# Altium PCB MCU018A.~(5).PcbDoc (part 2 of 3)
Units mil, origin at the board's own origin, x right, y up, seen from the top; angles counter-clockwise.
Board outline 4035 x 4400 mil, 2 copper layers (Top Layer, Bottom Layer), stack 62 mil thick; 269 components, 230 nets, 958 pads, 568 vias.

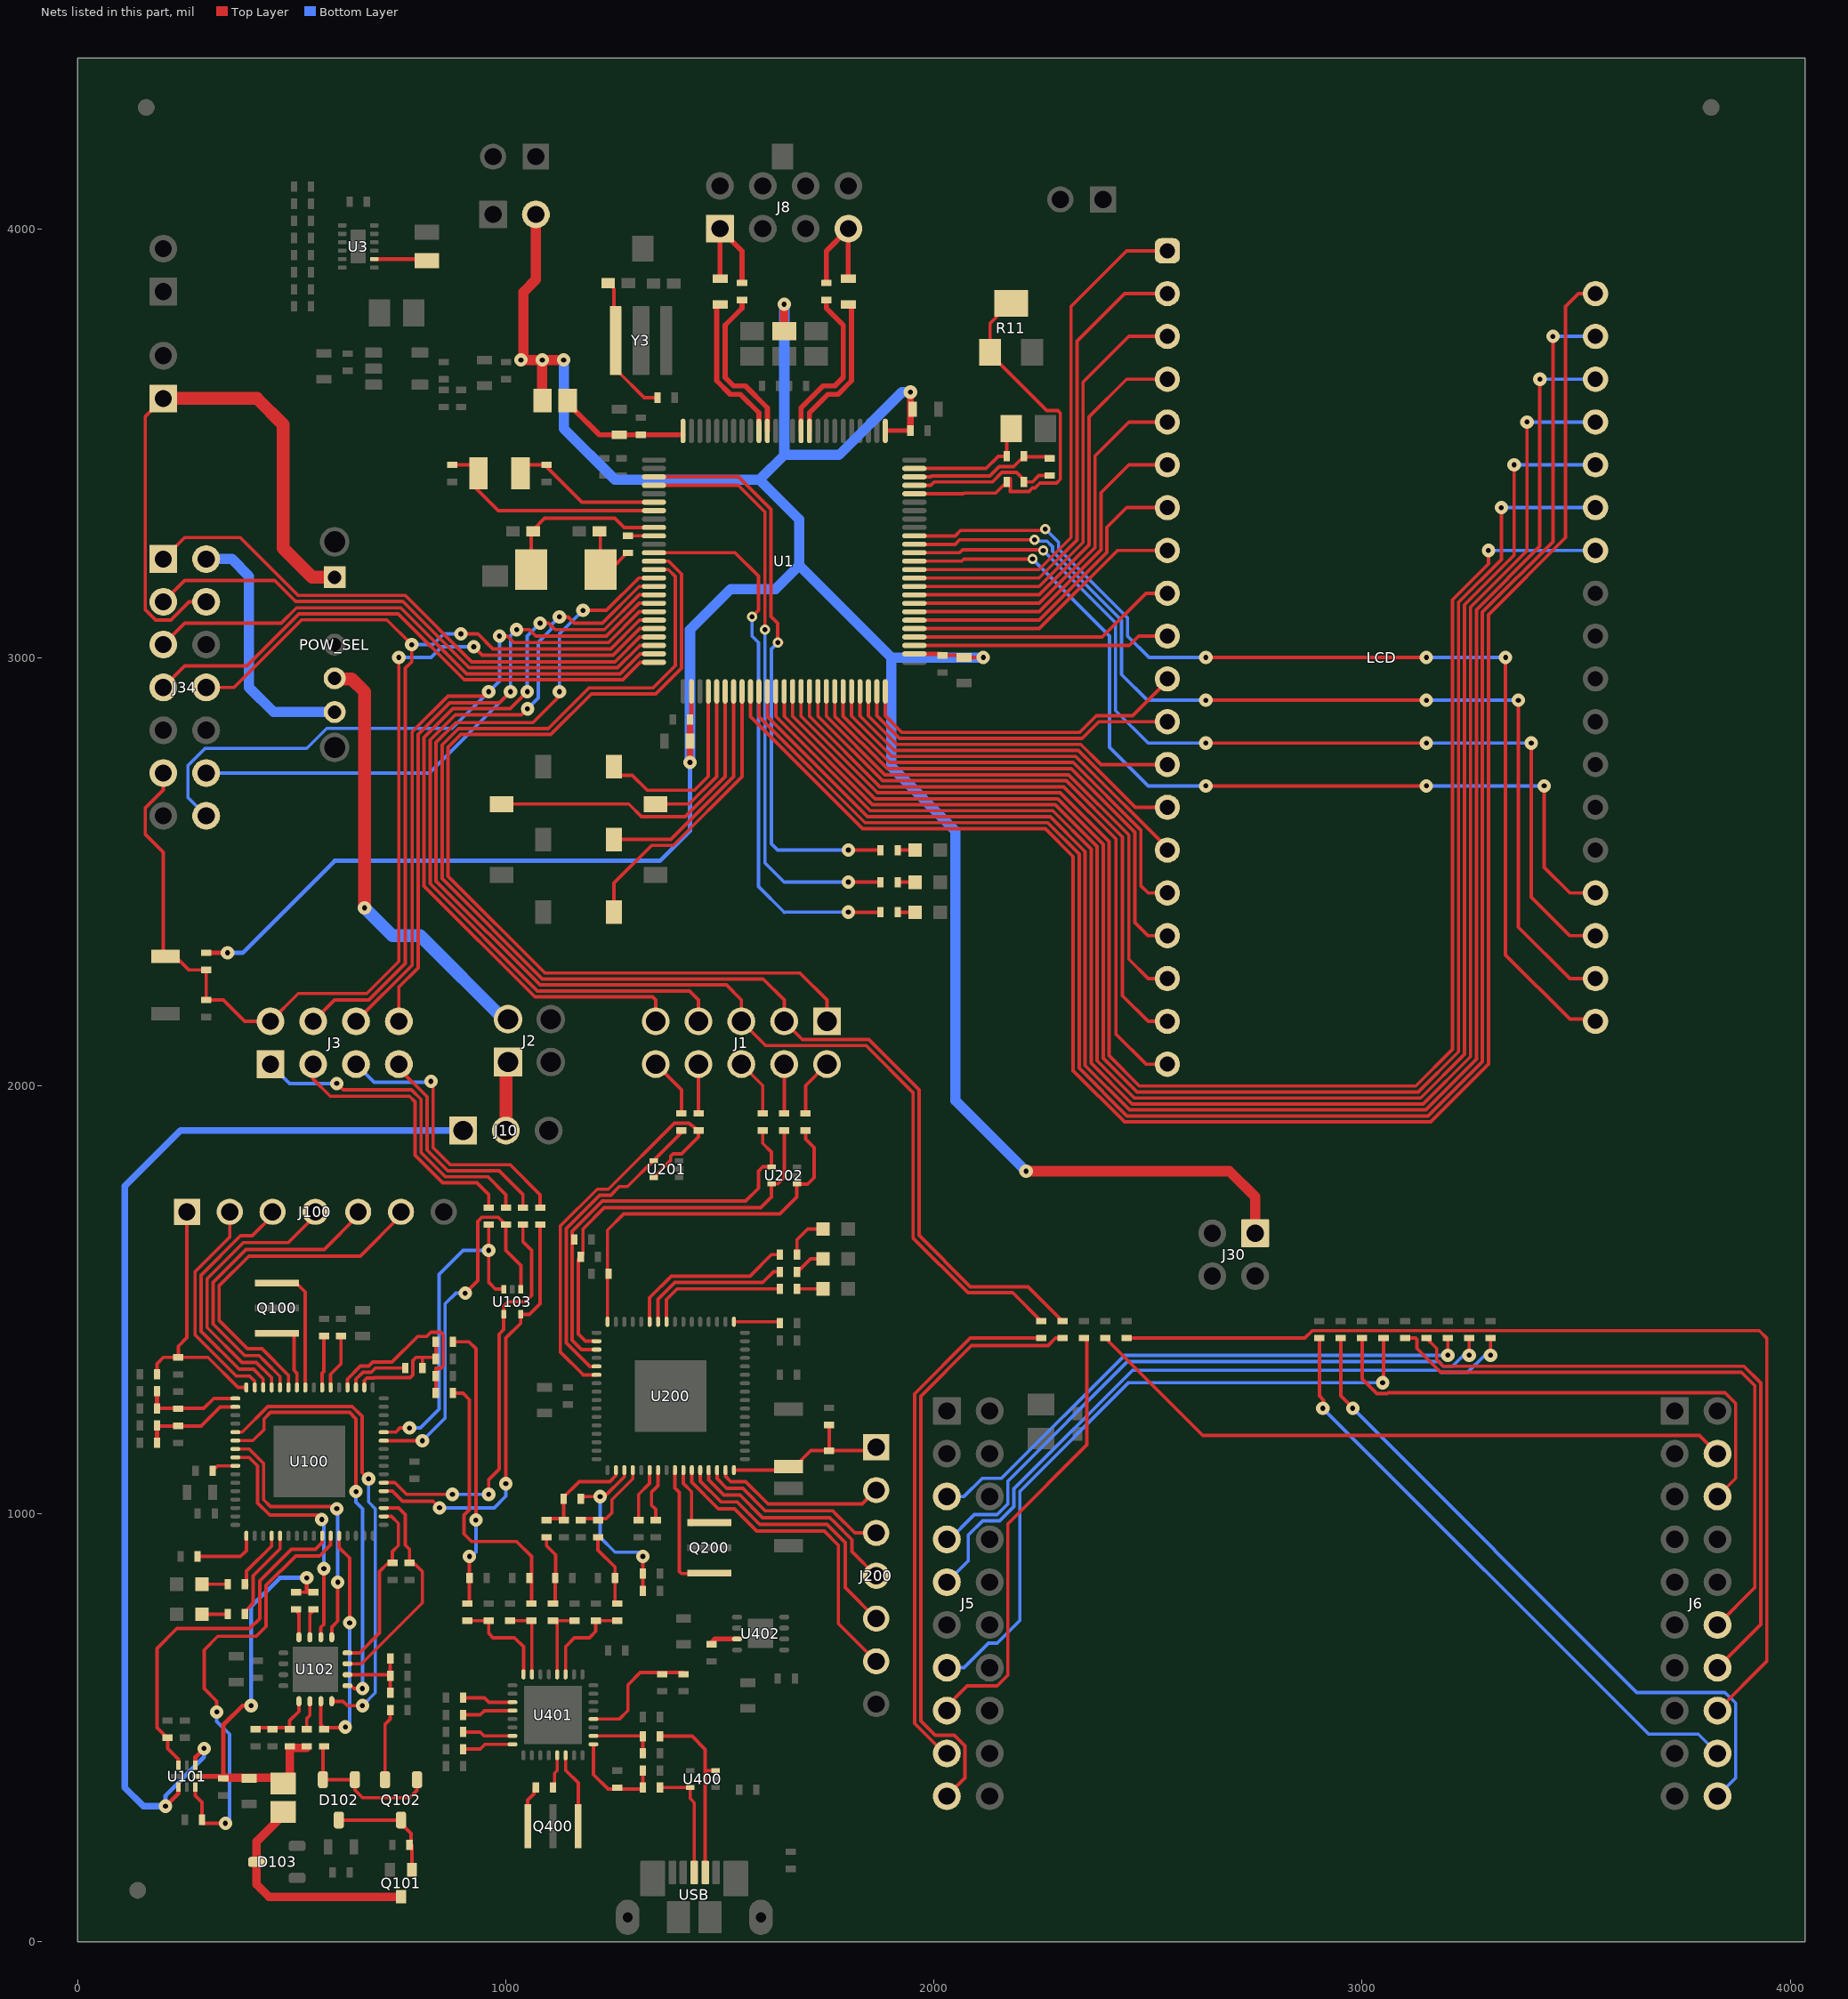
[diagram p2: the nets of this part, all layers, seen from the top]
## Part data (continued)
R15 R26 R100 R101 R201 R203: "RES, 22, 5%, 0.063 W, 0402", Manufacturer=Vishay-Dale, Power_W=0.063, Supplier Part Number 1=541-22JCT-ND, TempCo="200 ppm/C", Tolerance_%=5, Value1=5%, Value2=0.063W, Value_Code=22R0, ValueDisplayed=22
R16 R17: "RES, 200, 1%, 0.063 W, 0402", Manufacturer=Vishay-Dale, Power_W=0.063, Supplier Part Number 1=541-200LCT-ND, TempCo="100 ppm/C", Tolerance_%=1, Value1=1%, Value2=0.063W, Value_Code=200R, ValueDisplayed=200
R18 R121 R123: "RES, 47 k, 5%, 0.063 W, 0402", Manufacturer=Vishay-Dale, Power_W=0.063, Supplier Part Number 1=541-47KJCT-ND, TempCo="200 ppm/C", Tolerance_%=5, Value1=5%, Value2=0.063W, Value_Code=47k0, ValueDisplayed=47k
R19: "RES, 0, 5%, 0.125 W, 0805", Manufacturer=Vishay-Dale, Power_W=0.125, Supplier Part Number 1=541-0.0ACT-ND, TempCo="200 ppm/C", Tolerance_%=5, Value1=5%, Value2=0.125W, Value_Code=0000, ValueDisplayed=0
R20 R21 R22 R41 R42 R43 R44 R45 R46 R47 R48 R49: library part Resistor, "RES, xxx ohm, x%, xW, [PackageReference]", Alternate Manufacturer=-
R23 R24: "RES, 390, 5%, 0.063 W, 0402", Manufacturer=Vishay-Dale, Power_W=0.063, Supplier Part Number 1=541-390JCT-ND, TempCo="200 ppm/C", Tolerance_%=5, Value1=5%, Value2=0.063W, Value_Code=390R, ValueDisplayed=390
R25 R120 R205: "RES, 470, 5%, 0.063 W, 0402", Manufacturer=Vishay-Dale, Power_W=0.063, Supplier Part Number 1=541-470JCT-ND, TempCo="200 ppm/C", Tolerance_%=5, Value1=5%, Value2=0.063W, Value_Code=470R, ValueDisplayed=470
R27 R28 R29 R30 R31 R32 R33 R34 R35 R36 R37 R38 R50 R51 R124: "RES, 0, 5%, 0.063 W, 0402", Manufacturer=Vishay-Dale, Power_W=0.063, Supplier Part Number 1=541-0.0JCT-ND, TempCo="200 ppm/C", Tolerance_%=5, Value1=5%, Value2=0.063W, Value_Code=0000, ValueDisplayed=0
R103 R206: "RES, 1.5 k, 5%, 0.063 W, 0402", Manufacturer=Vishay-Dale, Power_W=0.063, Supplier Part Number 1=71-CRCW0402J-1.5K-E3, TempCo="200 ppm/C", Tolerance_%=5, Value1=5%, Value2=0.063W, Value_Code=1k50, ValueDisplayed=1.5k
R104: "RES, 470, 5%, 0.063 W, 0402", Manufacturer=Vishay-Dale, Power_W=0.063, Supplier Part Number 1=541-470JCT-ND, TempCo="200 ppm/C", Tolerance_%=5, Value1=5%, Value2=0.063W, Value_Code=470R
R105 R202 R204: "RES, 390 ohm, 5%, 0.063W, 0402", Manufacturer=Vishay-Dale, Power_W=0.063, Supplier Part Number 1=541-390JCT-ND, TempCo="200 ppm/C", Tolerance_%=5, Value1=5%, Value2=0.063W, Value_Code=390R
R106 R209 R404: "RES, 47 k, 5%, 0.063 W, 0402", Manufacturer=Vishay-Dale, Power_W=0.063, Supplier Part Number 1=541-47KJCT-ND, TempCo="200 ppm/C", Tolerance_%=5, Value1=5%, Value2=0.063W, Value_Code=47k0
R107 R108 R116 R117 R118 R119: "RES, 221 k, 1%, 0.063 W, 0402", Manufacturer=Vishay-Dale, Power_W=0.063, Supplier Part Number 1=541-221KLCT-ND, TempCo="100 ppm/C", Tolerance_%=1, Value1=1%, Value2=0.063W, Value_Code=221k
R109: "RES, 150 k, 1%, 0.063 W, 0402", Manufacturer=Vishay-Dale, Power_W=0.063, Supplier Part Number 1=541-150KLCT-ND, TempCo="100 ppm/C", Tolerance_%=1, Value1=1%, Value2=0.063W, Value_Code=150k
R110: "RES, 240 k, 1%, 0.063 W, 0402", Manufacturer=Vishay-Dale, Power_W=0.063, Supplier Part Number 1=541-240KLCT-ND, TempCo="100 ppm/C", Tolerance_%=1, Value1=1%, Value2=0.063W, Value_Code=240k
R111 R112: "RES, 4.7 k, 5%, 0.063 W, 0402", Manufacturer=Vishay-Dale, Power_W=0.063, Supplier Part Number 1=541-4.7KJCT-ND, TempCo="200 ppm/C", Tolerance_%=5, Value1=5%, Value2=0.063W, Value_Code=4k70, ValueDisplayed=4.7k
R113: "RES, 2.20 k, 1%, 0.063 W, 0402", Manufacturer=Vishay-Dale, Power_W=0.063, Supplier Part Number 1=541-2.20KLCT-ND, TempCo="100 ppm/C", Tolerance_%=1, Value1=1%, Value2=0.063W, Value_Code=2k20, ValueDisplayed=2.20k
R114: "RES, 6.81 k, 1%, 0.063 W, 0402", Manufacturer=Vishay-Dale, Power_W=0.063, Supplier Part Number 1=541-6.81KLCT-ND, TempCo="100 ppm/C", Tolerance_%=1, Value1=1%, Value2=0.063W, Value_Code=6k81, ValueDisplayed=6.81k
R115: "RES, 3.32 k, 1%, 0.063 W, 0402", Manufacturer=Vishay-Dale, Power_W=0.063, Supplier Part Number 1=541-3.32KLCT-ND, TempCo="100 ppm/C", Tolerance_%=1, Value1=1%, Value2=0.063W, Value_Code=3k32, ValueDisplayed=3.32k
R122: "RES, 820, 5%, 0.063 W, 0402", Manufacturer=Vishay-Dale, Power_W=0.063, Supplier Part Number 1=541-820JCT-ND, TempCo="200 ppm/C", Tolerance_%=5, Value1=5%, Value2=0.063W, Value_Code=820R, ValueDisplayed=820
R200 R208: "RES, 2.2 k, 5%, 0.063 W, 0402", Manufacturer=Vishay-Dale, Power_W=0.063, Supplier Part Number 1=541-2.2KJCT-ND, TempCo="200 ppm/C", Tolerance_%=5, Value1=5%, Value2=0.063W, Value_Code=2k20, ValueDisplayed=2.2k
R207 R418: "RES, 10 k, 5%, 0.063 W, 0402", Manufacturer=Vishay-Dale, Power_W=0.063, Supplier Part Number 1=541-10KJCT-ND, TempCo="200 ppm/C", Tolerance_%=5, Value1=5%, Value2=0.063W, Value_Code=10k0, ValueDisplayed=10k
R210: "RES, 1.0 M, 5%, 0.063 W, 0402", Manufacturer=Vishay-Dale, Power_W=0.063, Supplier Part Number 1=541-1.0MJCT-ND, TempCo="200 ppm/C", Tolerance_%=5, Value1=5%, Value2=0.063W, Value_Code=1M00, ValueDisplayed=1.0M
R400 R410: library part CMP-0026842-3, "RES, 15 k, 5%, 0.063 W, AEC-Q200 Grade 0, 0402", Manufacturer=Vishay-Dale, Power_W=63mW, Supplier Part Number 1=541-15KJCT-ND, TempCo="200 ppm/C", Tolerance_%=5%, Value2=0.063W, Value_Code=15k0, ValueDisplayed=15k
R401 R402 R403 R405 R411 R412: "RES, 15 k, 5%, 0.063 W, 0402", Manufacturer=Vishay-Dale, Power_W=0.063, Supplier Part Number 1=541-15KJCT-ND, TempCo="200 ppm/C", Tolerance_%=5, Value1=5%, Value2=0.063W, Value_Code=15k0, ValueDisplayed=15k
R406: "RES, 27 ohm, 5%, 0.063W, 0402", Manufacturer=Vishay-Dale, Power_W=0.063, Supplier Part Number 1=541-27JCT-ND, TempCo="200 ppm/C", Tolerance_%=5, Value1=5%, Value2=0.063W, Value_Code=27R0
R407 R409 R413 R414 R415 R416: "RES, 22 ohm, 5%, 0.063W, 0402", Manufacturer=Vishay-Dale, Power_W=0.063, Supplier Part Number 1=541-22JCT-ND, TempCo="200 ppm/C", Tolerance_%=5, Value1=5%, Value2=0.063W, Value_Code=22R0
R408: "RES, 1.5 k, 5%, 0.063 W, 0402", Manufacturer=Vishay-Dale, Power_W=0.063, Supplier Part Number 1=541-1.5KJCT-ND, TempCo="200 ppm/C", Tolerance_%=5, Value1=5%, Value2=0.063W, Value_Code=1k50
RUSB: "RES, 33 ohm, 5%, 0.063W, 0402", Manufacturer=Vishay-Dale, Power_W=0.063, Supplier Part Number 1=541-33JCT-ND, TempCo="200 ppm/C", Tolerance_%=5, Value1=5%, Value2=0.063W, Value_Code=33R0
SH-10 SH-J1 SH-J2 SH-J3 SH-J4 SH-J5 SH-J6 SH-J7 SH-J8 SH-J9 SH-J11: "Shunt, 2.54mm, Gold, Black", Manufacturer="Wurth Elektronik", Supplier Part Number 1=732-2678-ND
U1: "Mixed-Signal Microcontroller, PZ0100A (LQFP-100)", Alternate Manufacturer="Texas Instruments", Alternate PartNumber=MSP430FR6047IPZ
U2: "Single Output LDO, 150 mA, Adjustable 1.22 to 5.25 V Output, 2.2 to 5.5 V Input, with 500 nA Quiescent Current, 5-pin SOT (DDC), -40 to 125 degC, Green (RoHS & no Sb/Br)", Alternate Manufacturer="Texas Instruments", Alternate PartNumber=Equivalent, Dynamic Voltage Scaling=TRUE, Supplier Part Number 1=296-23331-2-ND
U3: "360nA IQ Step Down Converter for Low Power Applications, DSS0012A", Alternate Manufacturer="Texas Instruments", Alternate PartNumber=TPS62740DSST
U100 U200: "Mixed Signal MicroController, RGC0064B", Alternate Manufacturer="Texas Instruments", Alternate PartNumber=MSP430F5528IRGCT, Frequency(MHz)=25, Supplier Part Number 1=296-27305-2-ND, Temp Sensor=Yes
U101: library part CMP-0074338-2, "0.75-Ohm DUAL SPST ANALOG SWITCH WITH 1.8-V COMPATIBLE INPUT LOGIC, RSE0008A (UQFN-8)", Alternate Manufacturer="Texas Instruments"
U102: library part CMP-0039612-1, "16 MHz Mixed Signal Microcontroller with 8 KB Flash, 256 B SRAM and 16 GPIOs, 16-pin QFN (RSA), Green (RoHS & no Sb/Br)", Frequency(MHz)=16, Manufacturer="Texas Instruments", Temp Sensor=Yes
U103 U201 U202: "Low-Capacitance Array with + / - 15 kV ESD Protection, 4 Channels, -40 to +85 degC, 5-pin SOT (DRL), Green (RoHS & no Sb/Br)", Alternate Manufacturer="Texas Instruments", Alternate PartNumber=Equivalent, Breakdown Voltage(Min)(V)=6, IO Capacitance(Typ)(pF)=11, IO Leakage Current(nA)=100, Supplier Part Number 1=296-25866-2-ND
U400: "Low-Capacitance + / - 15 kV ESD-Protection Array for High-Speed Data Interfaces, 2 Channels, -40 to +85 degC, 5-pin SOT (DRL), Green (RoHS & no Sb/Br)", Alternate Manufacturer=None, Alternate PartNumber=Equivalent, Breakdown Voltage(Min)(V)=11, IO Capacitance(Typ)(pF)=1.5, IO Leakage Current(nA)=1, Manufacturer="Texas Instruments", Supplier Part Number 1=296-21883-2-ND
U401: "4-Port Full-Speed USB Hub, 3.3V, -40 to 85 degC, 32-Pin QFN (RHB), Green (RoHS & no Sb/Br)", Alternate Manufacturer=None, Alternate PartNumber=Equivalent, Manufacturer="Texas Instruments", Supplier Part Number 1=296-21926-2-ND, Supply Voltage(s)(V)=3.3
U402: "Single Output High PSRR LDO, 500 mA, Fixed 3.3 V Output, 2.7 to 6.5 V Input, with Low IQ, 8-pin SON (DRB), -40 to 125 degC, Green (RoHS & no Sb/Br)", Alternate Manufacturer="Texas Instruments", Alternate PartNumber=Equivalent, Supplier Part Number 1=TPS73533DRBR-ND
USB: "Receptacle, USB 2.0, Micro B, 5 Position, R/A, SMT", Color=Black, Current_A=1.8, Manufacturer=Molex, Supplier Part Number 1=WM11263CT-ND, Voltage_V=30
Y1: "Crystal, 8MHz, SMD", Frequency=8MHz, Frequency Stability=±30ppm, Manufacturer="Abracon Corporation", Supplier Part Number 1=535-10630-1-ND
Y2: "CRYSTAL, 32.768KHZ, 9PF, SMD", Frequency=32.768kHz, Frequency Stability=±20ppm, Manufacturer="Abracon Corporation", Supplier Part Number 1=535-9544-1-ND
Y3: "Ceramic Resonator, 8MHz, 22pF, SMD", Frequency=8MHz, Manufacturer="Abracon Corporation", Supplier Part Number 1=535-10004-1-ND
ZZ2 ZZ3 ZZ4: library part AssemblyNote, Alternate Manufacturer=-

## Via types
v1: diameter 23.62, hole 11.81, Top Layer to Bottom Layer, tented both sides, 344 vias
v2: diameter 31.5, hole 11.81, Top Layer to Bottom Layer, tented both sides, 181 vias
v3: diameter 19.68, hole 7.87, Top Layer to Bottom Layer, tented both sides, 35 vias
v4: diameter 19.68, hole 7.87, Top Layer to Bottom Layer, 8 vias

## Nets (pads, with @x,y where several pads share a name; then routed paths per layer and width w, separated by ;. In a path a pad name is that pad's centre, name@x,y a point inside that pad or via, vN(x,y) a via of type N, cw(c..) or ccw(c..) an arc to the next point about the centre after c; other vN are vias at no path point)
AVCC1: C1.1 C22.1 L1.1 U1.100 | length 289.6
  Top Layer w8: U1.100@1414.09,3520 U1.100@1414.09,3529.13
  Top Layer w12: L1.1@1158.46,3580 1218.46,3520 C22.1@1265,3520 C1.1@1315,3520 U1.100@1414.09,3520
BUT_DOWN: BUT_DOWN.2 U1.31 | length 772.5
  Top Layer w8: BUT_DOWN.2@990,2657.68 1287.11,2657.67 1316.91,2627.87 1418.28,2627.87 1512.2,2721.8 U1.31@1512.2,2920.87
BUT_LEFT: BUT_LEFT.2 U1.29 | length 446.8
  Top Layer w8: BUT_LEFT.2@1252.67,2724.99 1295.01,2724.99 1330,2690 1440.8,2690 1472.83,2722.03 U1.29@1472.83,2920.87
BUT_RIGHT: BUT_RIGHT.2 U1.33 | length 664.3
  Top Layer w8: BUT_RIGHT.2@1252.67,2410 1252.67,2473.25 1340.42,2561 1391,2561 1551.57,2721.57 U1.33@1551.57,2920.87
BUT_SELECT: BUT_SELECT.2 U1.32 | length 550
  Top Layer w8: BUT_SELECT.2@1252.68,2575 1252.67,2582.67 1260.34,2575 1385.2,2575 1531.89,2721.69 U1.32@1531.89,2920.87
BUT_UP: BUT_UP.2 U1.30 | length 368.1
  Top Layer w8: BUT_UP.2@1350,2657.68 1428.27,2657.67 1492.52,2721.92 U1.30@1492.52,2920.87
CH0_IN: C11.1 U1.91 | length 348.9
  Top Layer w12: C11.1@1492.52,3823.43 1492.52,3646.26 1524.02,3614.76 1547.64,3614.76 1590.94,3571.46 U1.91@1590.94,3529.13
CH0_OUT: R16.2 U1.90 | length 379
  Top Layer w12: R16.2@1551.57,3834.92 1551.57,3815.55 1512.2,3776.18 1512.2,3654.13 1531.89,3634.45 1559.45,3634.45 1610.63,3583.27 U1.90@1610.63,3529.13
CH1_IN: C12.1 U1.85 | length 356.8
  Top Layer w12: U1.85@1709.06,3529.13 1709.06,3571.46 1752.36,3614.76 1775.98,3614.76 1807.48,3646.26 1807.48,3823.43 C12.1@1799.61,3823.43
CH1_OUT: R17.2 U1.86 | length 379
  Top Layer w12: U1.86@1689.37,3529.13 1689.37,3583.27 1740.55,3634.45 1768.11,3634.45 1787.8,3654.13 1787.8,3776.18 1748.43,3815.55 R17.2@1748.43,3834.92
COMM_IRQ: J1.1 U1.13 | length 2273.4
  Top Layer w8: U1.13@1346.18,3225 1380,3225 1410,3195 1410,2975.2 1349.8,2915 1199.8,2915 1104.8,2820 895,2820 865,2790 865,2489.2 1091.2,2263 1687,2263 1750,2200 J1.1@1750,2150
COMM_RXD: J1.7 U1.16 | length 1891.6
  Top Layer w8: v2(1050.5,2880) 1036.75,2866.25 881.86,2866.25 823,2807.4 823,2471.8 1073.8,2221 1429,2221 1450,2200 J1.7@1450,2150 ; v2(1125,3095) 1145,3095 1160,3080 1225,3080 1310.94,3165.94 U1.16@1345.87,3165.94 U1.16@1346.18,3165.94
  Bottom Layer w8: v2(1050.5,2880) 1075.75,2905.25 1075.75,3035.75 1106,3066 1106,3076 v2(1125,3095)
COMM_SCL: J1.5 R50.1 U1.15 | length 3153.5
  Top Layer w8: v2(1125,2920) 1125,2910 1063,2848 883.4,2848 837,2801.6 837,2477.6 1079.6,2235 1515,2235 1550,2200 J1.5@1550,2150 1606.48,2093.52 1841.68,2093.52 1951,1984.2 1951,1644.2 2079.2,1516 2184,1516 R50.1@2250,1450 ; v2(1180,3110) 1235,3110 1310.63,3185.63 U1.15@1345.87,3185.63 U1.15@1346.18,3185.63
  Bottom Layer w8: v2@1115.75,2920 v2(1125,2920) 1125,3055 v2(1180,3110)
COMM_SDA: J1.3 R51.1 U1.14 | length 3304.2
  Top Layer w8: U1.14@1346.18,3205.31 1379.68,3205.31 1396,3189 1396,2981 1344,2929 1194,2929 1099,2834 889.2,2834 851,2795.8 851,2483.4 1085.4,2249 1601,2249 1650,2200 J1.3@1650,2150 1692.48,2107.52 1847.48,2107.52 1965,1990 1965,1650 2085,1530 2220,1530 R51.1@2300,1450
COMM_TXD: J1.9 U1.17 | length 1812.1
  Top Layer w8: v2(1050,2920) 1010.25,2880.25 876.06,2880.25 809,2813.2 809,2466 1068,2207 1343,2207 1350,2200 J1.9@1350,2150 ; v2(1080,3080) 1100,3080 1115,3065 1230,3065 1311.26,3146.26 U1.17@1345.87,3146.26 U1.17@1346.18,3146.26
  Bottom Layer w8: v2(1050,2920) 1050,3050 v2(1080,3080)
D+: R407.1 U400.5 USB.3 | length 245.7
  Top Layer w8: R407.1@1363.62,360 1363.94,360.31 U400.5@1430.47,360.31 1430.47,334.53 1440,325 USB.3@1440,185.51
D-: R409.1 U400.3 USB.2 | length 402.5
  Top Layer w8: R409.1@1363.62,480 1435,480 1465.59,449.41 1465.59,399.68 ; USB.2@1465.59,185.51 1465.59,399.68 ; U400.3@1489.53,399.68 1465.59,399.68
DM0: C404.1 R409.2 U401.2 | length 152.7
  Top Layer w8: U401.2@1204.49,480.79 1316.38,480.79 R409.2@1316.38,480 ; C404.1@1320,440 R409.2@1320,480
DM1: C407.1 R414.2 U401.11 | length 225.2
  Top Layer w8: U401.11@1139.53,624.49 1139.53,689.53 1160,710 1195,710 1210,725 C407.1@1210,750 R414.2@1260,750
DM2: C401.1 R415.2 U401.15 | length 175.5
  Top Layer w8: C401.1@1010,750 R415.2@1060,750 ; U401.15@1060.79,624.49 R415.2@1060.79,750
DM3: R401.1 U401.19 | length 116.2
  Top Layer w8: R401.1@903.62,570 950,570 960.47,559.53 U401.19@1015.51,559.53
DM4: R403.1 U401.23 | length 115.7
  Top Layer w8: R403.1@903.62,490 940,490 949.21,480.79 U401.23@1015.51,480.79
DP0: C403.1 R407.2 R408.1 U401.1 | length 241.7
  Top Layer w8: U401.1@1204.49,461.1 1204.49,390.51 1238.62,356.38 1312.76,356.38 1316.38,360 R407.2@1320,360 C403.1@1320,400
DP1: C406.1 R413.2 U401.12 | length 172
  Top Layer w8: R413.2@1110,750 C406.1@1160,750 ; U401.12@1119.84,624.49 1119.84,746.22 R413.2@1120,746.38
DP2: C405.1 R416.2 U401.16 | length 236.3
  Top Layer w8: R416.2@910,750 956.38,750 960,746.38 960,720 970,710 1020,710 1041.1,688.9 U401.16@1041.1,624.49
DP3: R400.2 U401.20 | length 116
  Top Layer w8: R400.2@903.62,530 940,530 949.84,539.84 U401.20@1015.51,539.84
DP4: R402.1 U401.24 | length 116.5
  Top Layer w8: R402.1@903.62,450 940,450 951.1,461.1 U401.24@1015.51,461.1
DVCC1: C2.2 C5.1 C6.1 C25.1 C26.1 C27.2 J30.1 J32.2 L1.2 L2.2 R18.2 U1.27 U1.52 U1.76 | length 7327.6
  Top Layer w8: C2.2@2020,3005 2065,3005 C27.2@2070,3000 v2(2115,3000)
  Top Layer w10: R18.2@300,2310 v2(350,2310) ; C6.1@1430,2855 1433.46,2858.46 U1.27@1433.46,2920.87 ; U1.76@1886.54,3529.13 1887.4,3530 C5.1@1945,3530 ; U1.52@1954.45,3008.46 2016.54,3008.46 C2.2@2020,3005
  Top Layer w15: v2(1430,2755) C25.1@1430,2805 C6.1@1430,2855 ; C5.1@1945,3530 v2(1945,3620) ; v2@2110,3005 v2(2115,3000)
  Top Layer w20: L2.2@1650,3758.46 v2(1650,3825)
  Top Layer w24: v2(1035,3695) v2(1085,3695) ; v2@1041.25,3706.25 1041.25,3853.98 1070,3882.73 J32.2@1070,4035 ; L1.2@1085,3586.54 v2(1085,3695) ; v2(1135,3695) v2(1085,3695) ; v2(2215,1800) 2690,1800 2750,1740 J30.1@2750,1655
  Bottom Layer w10: v2(350,2310) 385,2310 600,2525 1360,2525 1430,2595 v2(1430,2755)
  Bottom Layer w24: v2(1135,3695) 1135,3535 1255,3415 1592.28,3415 ; v2(1430,2755) 1430,3065 1525,3160 1630,3160 1685,3215 ; v2(1650,3825) 1650.32,3824.69 1650.32,3473.03 ; v2(1945,3620) 1925,3620 1778.03,3473.03 1650.32,3473.03 ; v2(2115,3000) 1900,3000 ; v2(2215,1800) 2050,1965 2050,2595 1900,2745 1900,3000 ; 1592.28,3415 1650.32,3473.03 ; 1592.28,3415 1685,3322.28 1685,3215 ; 1685,3215 1900,3000
EXT_VCC: J33.1 J34.4 POW_SEL.1 | length 1422.8
  Top Layer w8: J33.1@200,3605 157.52,3562.52 157.52,3112.4 182.4,3087.52 217.6,3087.52 260.08,3130 J34.4@300,3130
  Top Layer w30: J33.1@200,3605 419,3605 480,3544 480,3255 547.52,3187.48 POW_SEL.1@600,3187.48
EZFET_AVBUS: C110.1 R109.2 R110.1 U100.1 | length 222.8
  Top Layer w8: C110.1@185,1246 294.5,1246 317.64,1269.13 U100.1@368.17,1269.13
  Top Layer w10: C110.1@185,1256 R109.2@185,1286
EZFET_AVCC: C115.1 R118.2 R119.2 U102.6 | length 180.2
  Top Layer w8: U102.6@629.8,623.7 C115.1@730,623.7 ; R119.2@730,581.5 C115.1@730,621.5 C115.1@730,623.7 ; R118.2@730,661.5 C115.1@730,623.7
EZFET_AVCCOUT: C114.1 R116.1 R117.2 U102.1 | length 150.5
  Top Layer w8: C114.1@415,500.12 455,500.12 495,500.12 495,516.5 516.61,538.11 U102.1@516.61,561.69
EZFET_AVCCOUT2ADC: C109.1 R107.2 R108.1 U100.2 | length 236.7
  Top Layer w8: R107.2@190,1204.62 288.12,1204.62 332.95,1249.45 U100.2@368.17,1249.45
  Top Layer w10: C109.1@185,1166 R107.2@185,1206
EZFET_DCDCCAL0: R113.1 U102.12 | length 64.3
  Top Layer w8: R113.1@510,772.87 516.61,766.26 U102.12@516.61,711.3
EZFET_DCDCCAL1: R115.2 U102.2 | length 64.6
  Top Layer w8: R115.2@535,500.12 535,521.5 542.2,528.7 U102.2@542.2,561.69
EZFET_DCDCCAL2: R114.1 U102.11 | length 64.8
  Top Layer w8: U102.11@542.2,711.3 542.2,765.08 R114.1@550,772.87
EZFET_DCDCIO0: U100.5 U102.4 | length 1109.1
  Top Layer w8: U100.5@368.17,1190.39 384.1,1190.39 444.2,1250.5 640.8,1250.5 664,1227.29 664,1096 v2@680,1080 ; U102.4@593.39,561.69 619.8,561.69 630,551.5 v2(665,551.5)
  Bottom Layer w8: v2(665,551.5) 695,581.5 695,1011.5 679.19,1027.31 v2(679.19,1081.5)
EZFET_DCDCIO1: U100.6 U102.5 | length 1004.1
  Top Layer w8: U100.6@368.17,1170.71 409.21,1170.71 435,1196.5 435,1221.5 450,1236.5 635,1236.5 650,1221.5 v2(650,1051.5) ; U102.5@629.8,598.11 638.39,598.11 645,591.5 v2(665,591.5)
  Bottom Layer w8: v2(650,1051.5) 650,1026.5 665,1011.5 v2(665,591.5)
EZFET_DCDCPULSE: R122.2 U100.28 U102.3 | length 576.3
  Top Layer w8: U102.3@567.8,561.69 567.8,507.32 575,500.12 623.62,500.12 v2(625,501.5) ; U100.28@610.31,948.27 610.31,921.19 635,896.5 v2(635,745)
  Bottom Layer w8: v2(625,501.5) 635,511.5 v2(635,745)
EZFET_DCDCRST: U100.7 U102.9 | length 651.3
  Top Layer w8: U100.7@368.17,1151.02 400.27,1151.02 434,1117.29 434,1032.5 450,1016.5 600,1016.5 v2(605,1011.5) ; U102.9@593.39,711.3 593.39,734.88 607.38,748.87 v2(607.38,840)
  Bottom Layer w8: v2(605,1011.5) 607.38,1009.12 v2(607.38,840)
EZFET_DCDCTEST: U100.8 U102.10 | length 592.7
  Top Layer w8: U100.8@368.17,1131.34 400.16,1131.34 420,1111.5 420,1025 448.5,996.5 560,996.5 v2(570,986.5) ; U102.10@567.8,711.3 567.8,734.29 575,741.5 v2(575,871.5)
  Bottom Layer w8: v2(570,986.5) 575,981.5 v2(575,871.5)
EZFET_DM: C101.1 R101.2 U100.52 | length 441
  Top Layer w8: U100.52@630,1295 630,1314.26 660.28,1344.54 679.7,1344.54 689.17,1354 734.2,1354 794.2,1414 815.26,1414 824.75,1423.5 848.04,1423.5 853.89,1417.64 853.89,1345.35 848.04,1339.5 836.39,1339.5 C101.1@836.39,1321.5 R101.2@836.39,1281.5
EZFET_DP: C100.1 R100.2 R103.2 U100.50 | length 288
  Top Layer w8: U100.50@670.17,1295.51 U100.50@669.38,1294.72 669.38,1310.92 675,1316.54 691.3,1316.54 ; 692.76,1318 776.64,1318 782.5,1323.86 782.5,1357.5 790,1365 805,1365 ; R103.2@805,1340 805,1365 ; C100.1@835,1365 805,1365 ; C100.1@836.39,1361.5 R100.2@836.39,1401.5
EZFET_HOSTSCL: R111.2 U100.35 U102.7 | length 519.7
  Top Layer w8: U102.7@629.8,649.29 662.8,649.29 805,791.5 805,865 785,885 R111.2@775,885 775,916.5 765,926.5 765,997.89 749.66,1013.23 U100.35@714.62,1013.23
EZFET_HOSTSDA: R112.2 U100.34 U102.8 | length 415.6
  Top Layer w8: U102.8@629.8,674.88 658.39,674.88 705,721.5 705,865 725,885 R112.2@735,885 735,911.5 749,925.5 749,977.5 732.95,993.54 U100.34@714.62,993.54
EZFET_LED1: R104.2 U100.20 | length 139.5
  Top Layer w8: R104.2@395.49,833.71 394.09,835.1 394.09,865.59 452.79,924.29 U100.20@452.79,948.27
EZFET_LED2: R105.2 U100.21 | length 215.6
  Top Layer w8: R105.2@394.09,765.1 394.09,774.94 410,790.85 410,855 472.48,917.48 U100.21@472.48,948.27
EZFET_PUR: R103.1 U100.51 | length 145.4
  Top Layer w8: U100.51@649.69,1294.72 649.69,1314.15 666.08,1330.54 685.5,1330.54 694.97,1340 R103.1@765,1340
EZFET_RST: C111.1 J100.1 R106.1 U100.64 | length 616.3
  Top Layer w8: C111.1@185,1326 185,1350 200,1365 R106.1@235,1365 ; J100.1@255,1705 255,1411 235,1391 R106.1@235,1365 ; U100.64@393.72,1294.72 374.53,1294.72 304.25,1365 R106.1@235,1365
EZFET_SBWTCK_TST: R2.1 U100.44 U103.3 | length 782.5
  Top Layer w8: U100.44@714.62,1190.39 743.12,1190.39 752.83,1200.1 v2(775,1200.1) ; R2.1@960,1675 v2(960,1615) 960,1540 975.47,1524.53 U103.3@995.32,1524.53
  Bottom Layer w8: v2(775,1200.1) 800.1,1200.1 844.13,1244.13 844.13,1559.13 900,1615 v2(960,1615)
EZFET_SBWTDIO_RST: R1.1 U100.43 U103.1 | length 911.3
  Top Layer w8: U100.43@714.62,1170.71 715.33,1170 v2@805,1170 ; v2(905,1515) 934.25,1544.25 934.25,1682.89 943.86,1692.5 982.5,1692.5 R1.1@1000,1675 1000,1615 1035,1580 U103.1@1035,1525
  Bottom Layer w8: v2(805,1170.1) 858.13,1223.23 858.13,1490 883.13,1515 v2(905,1515)
EZFET_TARGET_VCC: J2.1 J10.2 | length 150
  Top Layer w30: J10.2@1000,1900 J2.1@1000,2050
EZFET_TCK: J100.2 U100.63 | length 511.3
  Top Layer w8: J100.2@355,1696.5 355,1646.5 274,1565.5 274,1417.7 370.2,1321.5 401.39,1321.5 413.41,1309.48 U100.63@413.41,1294.72
EZFET_TDI: J100.4 U100.61 | length 650.4
  Top Layer w8: U100.61@452.79,1294.72 452.79,1317.55 417.1,1353.24 383.35,1353.24 302,1434.6 302,1548.6 386.65,1633.24 491.75,1633.24 J100.4@555,1696.5
EZFET_TDO: J100.5 U100.60 | length 733.8
  Top Layer w8: U100.60@472.48,1294.72 472.48,1320.41 436.39,1356.5 436.29,1356.5 423.67,1369.12 389.93,1369.12 316,1443.05 316,1540.15 393.22,1617.37 575.87,1617.37 J100.5@655,1696.5
EZFET_TEST: J100.6 U100.59 | length 817.2
  Top Layer w8: U100.59@492.17,1294.72 492.17,1323.17 430.35,1384.99 396.5,1384.99 330,1451.5 330,1531.7 399.8,1601.5 660,1601.5 J100.6@755,1696.5
EZFET_TMS: J100.3 U100.62 | length 567
  Top Layer w8: U100.62@433.1,1294.72 433.1,1314.79 410.52,1337.37 376.78,1337.37 288,1426.15 288,1557.05 380,1649.05 380,1649.12 407.62,1649.12 J100.3@455,1696.5
EZFET_UART_RXD: R4.1 U100.38 U103.4 | length 959.7
  Top Layer w8: U100.38@714.62,1072.28 740.61,1072.28 767.89,1045 v2(875,1045) ; v2(960,1045) 960,1080 984.13,1104.13 984.13,1419.13 995,1430 995,1465.16 U103.4@995.32,1465.47 995.32,1485.32 1005,1495 1045.51,1495 1060,1509.49 1060,1615 1040,1635 R4.1@1040,1674.57
  Bottom Layer w8: v2(875,1045) v2(960,1045)
EZFET_UART_TXD: R3.1 U100.37 U103.5 | length 992
  Top Layer w8: U100.37@714.62,1052.6 735.02,1052.6 758.99,1028.62 830,1028.62 v2(845,1013.62) ; v2(1000,1070) 1000,1410 1034.69,1444.69 U103.5@1034.69,1465.47 1035,1465.16 1055.16,1465.16 1080,1490 R3.1@1080,1674.57
  Bottom Layer w8: v2(845,1013.62) 972.69,1013.62 1000,1040.94 v2(1000,1070)
EZFET_V18: C106.1 U100.55 | length 118.3
  Top Layer w8: U100.55@570.93,1294.72 570.93,1328.38 575,1332.45 C106.1@575,1411.38
EZFET_VCC: J2.2 POW_SEL.3 | length 1027.7
  Top Layer w30: POW_SEL.3@600,2951.26 601.26,2950 640,2950 670,2920 v2(670,2415)
  Bottom Layer w30: v2(670,2415) 735,2350 800,2350 J2.2@1000,2150
EZFET_VCCEN1: R123.2 U100.26 U101.3 | length 849.3
  Top Layer w8: U101.3@235.32,412.09 235.32,426.18 210,451.5 210,475 185,500 185,685 231.5,731.5 401.5,731.5 425,755 425,842.63 498.86,916.5 555,916.5 570.93,932.43 U100.26@570.93,948.27
EZFET_VCCEN2: R121.2 U100.27 U101.7 | length 1054
  Top Layer w8: U101.7@274.68,360.91 274.68,340.87 290,325.56 R121.2@290,285 290,276.5 v2(345,276.5) ; v2(324.75,536.74) 324.75,561.74 295,591.5 295,681.5 327.13,713.62 417.13,713.62 440,736.5 440,832.35 509.14,901.5 565,901.5 590.62,927.12 U100.27@590.62,948.27
  Bottom Layer w8: v2(324.75,536.74) 324.75,514.67 354.5,484.92 354.5,286 v2(345,276.5)
EZFET_VCCOUT: C120.1 C121.1 L101.2 R113.2 R114.2 R115.1 R116.2 U101.8 | length 988.9
  Top Layer w8: R113.2@510,816.5 535,816.5 R114.2@550,816.5
  Top Layer w10: C121.1@340,385.12 340,506.5 385,551.5 v2(405,551.5) ; 535,816.5 v2(535,850)
  Top Layer w12: U101.8@280.59,386.5 C121.1@338.62,386.5
  Top Layer w20: C121.1@342.13,382.99 473.5,382.99 480,376.5 495,391.5 495,452.87 R115.1@535,452.87
  Bottom Layer w10: v2(405,551.5) 405,782.94 472.06,850 v2(535,850)
EZFET_VCCTARGET: J10.1 U101.1 U101.5 | length 2649.1
  Top Layer w10: v2(205,316.5) 235.32,346.81 U101.5@235.32,360.91 ; U101.1@274.68,412.09 274.68,431.18 v2(295,451.5)
  Bottom Layer w10: v2(205,316.5) 205,341.5 295,431.5 v2(295,451.5)
  Bottom Layer w15: v2(205,316.5) 153.5,316.5 110,360 110,1765 240,1895 295.64,1895 295.89,1895.25 320.11,1895.25 320.36,1895 395.64,1895 395.89,1895.25 420.11,1895.25 420.36,1895 495.64,1895 495.89,1895.25 520.11,1895.25 520.36,1895 595.64,1895 595.89,1895.25 620.11,1895.25 620.36,1895 695.64,1895 695.89,1895.25 720.11,1895.25 720.36,1895 895,1895 J10.1@905,1905
EZFET_VCORE: C107.1 U100.17 | length 150.2
  Top Layer w8: C107.1@283.62,900.1 380,900.1 393.72,913.82 U100.17@393.72,948.27
EZFET_VREF: C108.1 U100.9 | length 58
  Top Layer w8: C108.1@315,1100 326.65,1111.65 U100.9@368.17,1111.65
EZFET_VUSB: C105.1 U100.54 | length 126.8
  Top Layer w8: U100.54@590.62,1294.72 590.62,1325.62 615,1350 C105.1@615,1411.38
EZFET_XT2IN: Q100.1 U100.57 | length 253.7
  Top Layer w8: Q100.1@510,1539.49 531.55,1517.94 U100.57@531.55,1294.72
EZFET_XT2OUT: Q100.3 U100.58 | length 128.1
  Top Layer w8: Q100.3@505,1420 505,1335 511.86,1328.14 U100.58@511.86,1294.72
HFXIN: C16.1 U1.9 Y1.1 | length 389.3
  Top Layer w8: Y1.1@1059.29,3205 C16.1@1059.29,3294.29 ; C16.1@1065,3300 1090,3325 1254.72,3325 1275.98,3303.74 U1.9@1345.87,3303.74
HFXOUT: R26.2 U1.10 | length 61.6
  Top Layer w8: R26.2@1284.92,3284.37 U1.10@1346.54,3284.37
HID-BRIDGE_DM: C200.1 R201.2 U200.52 | length 198.1
  Top Layer w8: C200.1@1175,988.62 1234.12,988.62 1247.62,1002.12 1247.62,1032.62 1296.39,1081.39 U200.52@1296.39,1101.77
HID-BRIDGE_DP: C201.1 R203.2 R206.1 U200.50 | length 248.6
  Top Layer w8: R203.2@1095,988.62 1135,988.62 1135,1031.38 1131.38,1035 1171.38,1075 1242.98,1075 1257.02,1089.03 U200.50@1257.02,1101.77
HID-BRIDGE_IRQ: R40.1 R207.1 U200.32 U202.1 | length 884.2
  Top Layer w8: U200.32@1237.33,1448.23 1237.33,1662.32 1275,1700 1640,1700 1679.53,1739.53 U202.1@1679.53,1770.31 1679.84,1770 1705,1770 1720,1785 1720,1855 1700,1875 R40.1@1700,1895
HID-BRIDGE_LED3: R205.2 U200.25 | length 327.1
  Top Layer w8: U200.25@1375.16,1448.23 1375.16,1500.16 1400,1525 R205.2@1640,1525
HID-BRIDGE_LED4: R204.2 U200.26 | length 359.4
  Top Layer w8: U200.26@1355.46,1448.23 1355.46,1500.47 1395,1540 1600,1540 1625,1565 R204.2@1635.88,1565
HID-BRIDGE_LED5: R202.2 U200.27 | length 402
  Top Layer w8: U200.27@1335.78,1448.23 1335.78,1504.22 1386.55,1555 1570,1555 1620,1605 R202.2@1640,1605
HID-BRIDGE_PUR: R206.2 R210.2 R211.1 U200.51 | length 440
  Top Layer w8: R206.2@1175,1038.62 1178.62,1035 1183.62,1040 v2(1220,1040) 1230.43,1040 1276.7,1086.27 U200.51@1276.7,1101.77 ; R211.1@1320,813.62 R211.1@1320,820 R210.2@1320,860 v2(1320,900)
  Bottom Layer w8: v2(1220,1040) 1220,945 1255,910 1310,910 v2(1320,900)
HID-BRIDGE_RST: C210.1 J200.1 R209.1 S201.2 U200.64 | length 408.8
  Top Layer w8: U200.64@1532.68,1101.77 1644.84,1101.77 S201.2@1656.59,1113.52 ; S201.2@1660,1110.12 1675.12,1110.12 1712.05,1147.05 R209.1@1755,1147.05 ; C210.1@1755,1203.43 R209.1@1755,1147.05 ; J200.1@1865,1155 1857.05,1147.05 R209.1@1755,1147.05
HID-BRIDGE_RXD: R7.1 U200.38 U201.5 | length 989.8
  Top Layer w8: 1180,1325 1127,1378 1127,1671.6 1213.4,1758 1239.36,1758 1393.86,1912.5 1426.14,1912.5 1447.12,1897.12 R7.1@1447.62,1896.75 ; 1180.79,1324.21 U200.38@1211.77,1324.21 ; U201.5@1345.47,1785.31 1384.69,1824.53 1384.69,1834.73 1390.54,1840.59 1410.59,1840.59 1450,1880 R7.1@1450,1895
HID-BRIDGE_SCL: R8.1 R200.1 U200.35 U202.4 | length 965.7
  Top Layer w8: U200.35@1211.77,1383.27 1176.73,1383.27 1155,1405 1155,1660 1225,1730 1560,1730 1590,1760 1590,1800 1600,1810 1620.16,1810 U202.4@1620.47,1809.68 1620.47,1844.53 1600,1865 R8.1@1600,1895
HID-BRIDGE_SDA: R39.1 R208.1 U200.34 U202.5 | length 946.7
  Top Layer w8: U200.34@1211.77,1402.95 1186.05,1402.95 1169,1420 1169,1594 R208.1@1175,1600 1180,1605 1180,1665.2 1229.8,1715 1595,1715 1620,1740 1620,1769.84 U202.5@1620.47,1770.31 1635.31,1770.31 1650,1785 R39.1@1650,1895
HID-BRIDGE_TCK: J200.2 U200.63 | length 406.9
  Top Layer w8: U200.63@1512.99,1101.77 1512.99,1087.01 1525,1075 1560,1075 1612.46,1022.54 1832.54,1022.54 J200.2@1865,1055
HID-BRIDGE_TDI: J200.4 U200.61 | length 523.1
  Top Layer w8: U200.61@1473.61,1101.77 1473.61,1078.95 1509.3,1043.25 1546.85,1043.25 1599.31,990.8 1756.65,990.8 1764.2,983.25 1764.3,983.25 1808.42,939.13 1808.42,911.58 J200.4@1865,855
HID-BRIDGE_TDO: J200.5 U200.60 | length 631.3
  Top Layer w8: U200.60@1453.91,1101.77 1453.91,1076.09 1502.62,1027.38 1540.27,1027.38 1592.73,974.92 1750.08,974.92 1757.62,967.38 1757.72,967.38 1792.55,932.55 1792.55,827.45 J200.5@1865,755
HID-BRIDGE_TEST: J200.6 U200.59 | length 739.4
  Top Layer w8: U200.59@1434.22,1101.77 1434.22,1073.33 1496.05,1011.5 1533.7,1011.5 1586.16,959.05 1743.5,959.05 1776.68,925.87 1776.68,743.32 J200.6@1865,655
HID-BRIDGE_TMS: J200.3 U200.62 | length 444.3
  Top Layer w8: U200.62@1493.3,1101.77 1493.3,1081.7 1515.87,1059.13 1553.42,1059.13 1605.88,1006.67 1763.23,1006.67 1770.77,999.13 1770.87,999.13 1815,955 J200.3@1865,955
HID-BRIDGE_TXD: R6.1 U200.37 U201.4 | length 721.4
  Top Layer w8: U200.37@1211.77,1343.9 1196.1,1343.9 1185,1355 1141,1399.2 1141,1665.8 1219.2,1744 ; 1220,1744 1245.16,1744 1265.16,1764 1284,1764 1345,1825 R6.1@1410,1890
HID-BRIDGE_V18: C207.1 U200.55 | length 125.7
  Top Layer w8: C207.1@1350,986.63 1350,1010 1340,1020 1340,1050 1355.46,1065.47 U200.55@1355.46,1101.77
HID-BRIDGE_VCORE: C208.1 U200.17 | length 105
  Top Layer w8: U200.17@1532.68,1448.23 1633.15,1448.23 C208.1@1636.38,1445
HID-BRIDGE_VUSB: C206.1 U200.54 | length 123.8
  Top Layer w8: C206.1@1310,988.62 1310,1045 1335.78,1070.78 U200.54@1335.78,1101.77
HID-BRIDGE_XT2IN: Q200.1 U200.57 | length 273
  Top Layer w8: U200.57@1394.84,1101.77 1394.84,1060.16 1405,1050 1405,865 1410,860 Q200.1@1435,860
HID-BRIDGE_XT2OUT: Q200.3 U200.58 | length 135.6
  Top Layer w8: U200.58@1414.53,1101.77 1414.53,1070.47 1433.66,1051.34 Q200.3@1433.66,974.06
HUB_DM1: R201.1 R412.2 R414.1 | length 160.7
  Top Layer w8: R201.1@1215,941.38 1215,915 1255,875 R412.2@1255,850 ; R414.1@1255,793.62 R412.2@1255,846.38
HUB_DM2: R101.1 R405.2 R415.1 | length 646
  Top Layer w8: R101.1@880.02,1281.5 899.83,1281.5 915,1266.33 915,1009.06 902.38,996.44 902.38,952.62 920,935 1025,935 1060,900 R415.1@1060,793.62
HUB_DP1: R203.1 R411.2 R413.1 | length 153
  Top Layer w8: R203.1@1095,941.38 1095,925.2 1116.38,903.82 R411.2@1116.38,850 ; R413.1@1115,793.62 R411.2@1115,846.38
HUB_DP2: R100.1 R410.2 R416.1 | length 656.2
  Top Layer w8: R100.1@880.02,1401.5 913.5,1401.5 930,1385 v2(930,985) ; R416.1@915,793.62 R410.2@915,850 v2(915,900)
  Bottom Layer w8: v2(915,900) 930,910 v2(930,985)
HUB_R\E\S\E\T\: C400.1 R404.1 U401.4 | length 290.6
  Top Layer w8: U401.4@1204.49,520.16 1265.16,520.16 1285,540 1285,600 1313.62,628.62 C400.1@1415,628.62
HUB_XTAL1: Q400.1 U401.30 | length 177.7
  Top Layer w8: U401.30@1139.53,435.51 1139.53,400.47 1169.06,370.94 Q400.1@1169.06,270
HUB_XTAL2: R406.2 U401.29 | length 78.1
  Top Layer w8: R406.2@1113.62,360 1113.62,393.62 1119.84,399.84 U401.29@1119.84,435.51
JTAG_RESET: C14.1 J3.2 J34.11 MCU_RESET.2 R18.1 U1.21 | length 2506.2
  Top Layer w8: MCU_RESET.2@200,2315 200,2545.04 157.52,2587.52 157.52,2647.6 200,2690.08 J34.11@200,2730 ; MCU_RESET.2@205,2301.93 228.07,2301.93 260,2270 R18.1@300,2270 ; R18.1@300,2268.35 C14.1@300,2200 340,2200 390,2150 J3.2@450,2150 515,2215 675,2215 750,2290 v2(750,3000) ; v2(925,3025) 945,3005 1250,3005 1312.52,3067.52 U1.21@1345.87,3067.52 U1.21@1346.18,3067.52
  Bottom Layer w8: v2(750,3000) 825,3000 850,3025 v2(925,3025)
JTAG_RXD: J3.6 J34.14 U1.19 | length 2394.9
  Top Layer w8: J3.6@650,2150 781,2281 781,2826.2 864.8,2910 950,2910 v2(960,2920) ; v2(985,3050) 1003.59,3050 1018.59,3035 1240,3035 1311.89,3106.89 U1.19@1345.87,3106.89 U1.19@1346.18,3106.89
  Bottom Layer w8: J34.14@300,2630 257.52,2672.48 257.52,2747.6 282.4,2772.48 282.48,2772.48 297.52,2787.52 534.82,2787.52 581.59,2834.29 874.29,2834.29 v2(960,2920) 985,2945 v2(985,3050)
JTAG_TCK: J34.7 U1.25 | length 1298.1
  Top Layer w8: J34.7@200,2930 250,2980 395,2980 517,3102 748.6,3102 902.6,2948 1273,2948 1313.78,2988.78 U1.25@1345.87,2988.78 U1.25@1346.18,2988.78
JTAG_TDI: J34.3 U1.23 | length 1273
  Top Layer w8: J34.3@200,3130 250,3180 460,3180 509,3131 759.2,3131 914.2,2976 1261,2976 1313.15,3028.15 U1.23@1345.87,3028.15 U1.23@1346.18,3028.15
JTAG_TDO: J34.1 U1.22 | length 1311
  Top Layer w8: J34.1@200,3230 250,3280 379.8,3280 514.8,3145 765,3145 920,2990 1255,2990 1312.83,3047.83 U1.22@1345.87,3047.83 U1.22@1346.18,3047.83
JTAG_TEST: J3.4 J34.8 U1.20 | length 2210.5
  Top Layer w8: J34.8@300,2930 365,2930 523,3088 722,3088 v2(780,3030) 780,2990 765,2975 765,2285 680,2200 600,2200 J3.4@550,2150 ; v2(895,3055) 935,3055 970,3020 1245,3020 1312.2,3087.2 U1.20@1345.87,3087.2 U1.20@1346.18,3087.2
  Bottom Layer w8: v2(780,3030) 830,3030 855,3055 v2(895,3055)
JTAG_TMS: J34.5 U1.24 | length 1264.8
  Top Layer w8: J34.5@200,3030 250,3080 475,3080 511,3116 754.4,3116 908.4,2962 1267,2962 1313.46,3008.46 U1.24@1345.87,3008.46 U1.24@1346.18,3008.46
JTAG_TXD: J3.8 J34.12 U1.18 | length 2231.2
  Top Layer w8: J3.8@750,2150 750,2230 795,2275 795,2820.4 868.85,2894.25 985,2894.25 v2(1010.75,2920) ; v2(1025,3065) 1055,3065 1070,3050 1235,3050 1311.57,3126.57 U1.18@1345.87,3126.57 U1.18@1346.18,3126.57
  Bottom Layer w8: J34.12@300,2730 820.75,2730 v2(1010.75,2920) ; v2@1010.75,2934.33 1010.75,3050.75 v2(1025,3065)
JTAG_VCC: J34.2 POW_SEL.4 | length 600.4
  Bottom Layer w24: J34.2@300,3230 360,3230 400,3190 400,2930 457.48,2872.52 POW_SEL.4@600,2872.52
LCD0: LCD.1 U1.62 | length 1220.2
  Top Layer w8: U1.62@1954.45,3205.31 2245.11,3205.31 2320,3280.2 2320,3820 2450,3950 LCD.1@2550,3950
LCD1: LCD.2 U1.61 | length 1142.9
  Top Layer w8: U1.61@1954.45,3185.63 2245.23,3185.63 2334,3274.4 2334,3739 2445,3850 LCD.2@2550,3850
LCD2: LCD.3 U1.60 | length 1056.8
  Top Layer w8: U1.60@1954.45,3165.94 2245.34,3165.94 2348,3268.6 2348,3643 2455,3750 LCD.3@2550,3750
LCD3: LCD.4 U1.59 | length 979.5
  Top Layer w8: U1.59@1954.45,3146.26 2245.46,3146.26 2362,3262.8 2362,3562 2450,3650 LCD.4@2550,3650
LCD4: LCD.5 U1.58 | length 896.3
  Top Layer w8: U1.58@1954.45,3126.57 2245.57,3126.57 2376,3257.01 2376,3471 2455,3550 LCD.5@2550,3550
LCD5: LCD.6 U1.57 | length 816
  Top Layer w8: U1.57@1954.45,3106.89 2245.68,3106.89 2390,3251.21 2390,3385 2455,3450 LCD.6@2550,3450
LCD6: LCD.7 U1.56 | length 738.7
  Top Layer w8: U1.56@1954.45,3087.2 2245.8,3087.2 2404,3245.41 2404,3304 2450,3350 LCD.7@2550,3350
LCD7: LCD.8 U1.55 | length 671.1
  Top Layer w8: U1.55@1954.45,3067.52 2245.91,3067.52 2428.39,3250 LCD.8@2550,3250
LCD8: LCD.9 U1.54 | length 637.9
  Top Layer w8: U1.54@1954.45,3047.83 2392.83,3047.83 2495,3150 LCD.9@2550,3150
LCD9: LCD.10 U1.53 | length 604.6
  Top Layer w8: U1.53@1954.45,3028.15 2456.14,3028.15 2477.99,3050 LCD.10@2550,3050
LCD10: LCD.11 U1.50 | length 788.7
  Top Layer w8: U1.50@1886.22,2920.87 1886.22,2863.78 1925,2825 2340.2,2825 2379.2,2864 2464,2864 LCD.11@2550,2950
LCD11: LCD.12 U1.49 | length 778.6
  Top Layer w8: U1.49@1866.54,2920.87 1866.54,2863.67 1919.2,2811 2346,2811 2385,2850 LCD.12@2550,2850
LCD12: LCD.13 U1.48 | length 807.5
  Top Layer w8: U1.48@1846.85,2920.87 1846.85,2863.55 1913.4,2797 2343,2797 2390,2750 LCD.13@2550,2750
LCD13: LCD.14 U1.47 | length 868.7
  Top Layer w8: U1.47@1827.17,2920.87 1827.17,2863.44 1907.6,2783 2337,2783 2470,2650 LCD.14@2550,2650
LCD14: LCD.15 U1.46 | length 938.3
  Top Layer w8: U1.46@1807.48,2920.87 1807.48,2863.32 1901.8,2769 2331,2769 2550,2550 LCD.15@2544,2544
LCD15: LCD.16 U1.45 | length 1067.3
  Top Layer w8: U1.45@1787.8,2920.87 1787.8,2863.21 1896.01,2755 2325.2,2755 2483,2597.2 2483,2467 2500,2450 LCD.16@2550,2450
LCD16: LCD.17 U1.44 | length 1175.4
  Top Layer w8: U1.44@1768.11,2920.87 1768.11,2863.1 1891.21,2740 2320.4,2740 2469,2591.4 2469,2381 2500,2350 LCD.17@2550,2350
LCD17: LCD.18 U1.43 | length 1283.6
  Top Layer w8: U1.43@1748.43,2920.87 1748.43,2862.98 1885.41,2726 2314.6,2726 2455,2585.6 2455,2295 2500,2250 LCD.18@2550,2250
LCD18: LCD.19 U1.42 | length 1391.7
  Top Layer w8: U1.42@1728.74,2920.87 1728.74,2862.87 1879.61,2712 2308.8,2712 2440,2580.8 2440,2210 2500,2150 LCD.19@2550,2150
LCD19: LCD.20 U1.41 | length 1502.8
  Top Layer w8: U1.41@1709.06,2920.87 1709.06,2862.75 1873.81,2698 2303.01,2698 2425,2576.01 2425,2120 2495,2050 LCD.20@2550,2050
LCD20: LCD.32 U1.40 | length 3731
  Top Layer w8: U1.40@1689.37,2920.87 1689.37,2862.64 1868.01,2684 2294.79,2684 2409,2569.79 2409,2069.79 2479.79,1999 3125.21,1999 3211,2084.79 3211,3134.79 3295,3218.79 v2(3295,3250)
  Bottom Layer w8: v2(3295,3250) 3290,3250 LCD.32@3550,3250
LCD21: LCD.33 U1.39 | length 3846.4
  Top Layer w8: U1.39@1669.68,2920.87 1669.68,2862.53 1862.21,2670 2288.99,2670 2395,2563.99 2395,2063.99 2473.99,1985 3131.01,1985 3225,2078.99 3225,3128.99 3325,3228.99 v2(3325,3350)
  Bottom Layer w8: v2(3325,3350) 3330,3350 LCD.33@3550,3350
LCD22: LCD.34 U1.38 | length 3971.8
  Top Layer w8: U1.38@1650,2920.87 1650,2862.41 1856.41,2656 2283.2,2656 2381,2558.2 2381,2058.2 2468.2,1971 3136.8,1971 3239,2073.2 3239,3123.2 3355,3239.2 v2(3355,3450)
  Bottom Layer w8: v2(3355,3450) 3360,3450 LCD.34@3550,3450
LCD23: LCD.35 U1.37 | length 4097.1
  Top Layer w8: U1.37@1630.31,2920.87 1630.31,2862.3 1850.61,2642 2277.4,2642 2367,2552.4 2367,2052.4 2462.4,1957 3142.6,1957 3253,2067.4 3253,3117.4 3385,3249.4 v2(3385,3550)
  Bottom Layer w8: v2(3385,3550) LCD.35@3550,3550
LCD24: LCD.36 U1.36 | length 4231.9
  Top Layer w8: U1.36@1610.63,2920.87 1610.63,2862.19 1844.82,2628 2271.6,2628 2353,2546.6 2353,2046.6 2456.6,1943 3148.4,1943 3267,2061.6 3267,3111.6 3415,3259.6 v2@3415,3650 ; v2@3405.6,3650 v2(3415.3,3650)
  Bottom Layer w8: v2(3415.3,3650) LCD.36@3550,3650
LCD25: LCD.37 U1.35 | length 4347.5
  Top Layer w8: U1.35@1590.94,2920.87 1590.94,2862.07 1839.02,2614 2265.8,2614 2339,2540.8 2339,2040.8 2450.8,1929 3154.2,1929 3281,2055.8 3281,3105.8 3445.67,3270.47 v2(3445.67,3750)
  Bottom Layer w8: v2(3445.67,3750) LCD.37@3550,3750
LCD26: LCD.38 U1.34 | length 4455.7
  Top Layer w8: U1.34@1571.26,2920.87 1571.26,2861.96 1833.22,2600 2260,2600 2325,2535 2325,2035 2445,1915 3160,1915 3295,2050 3295,3100 3475,3280 3475,3820 3505,3850 LCD.38@3550,3850
LCD_COM0: LCD.24 U1.63 | length 2184.6
  Top Layer w8: U1.63@1954.13,3225 2065,3225 2070,3230 v1(2230,3230) ; v2(2635,2700) v2(3150,2700) ; v2(3425,2700) 3425,2510 3485,2450 LCD.24@3550,2450
  Bottom Layer w8: v1(2230,3230) 2410,3050 2410,2790 2500,2700 v2(2635,2700) ; v2(3150,2700) v2(3425,2700)
LCD_COM1: LCD.23 U1.64 | length 2300.8
  Top Layer w8: U1.64@1954.13,3244.69 2059.69,3244.69 2066.81,3251.81 v1@2253.19,3251.81 ; v2(2635,2800) v2(3150,2800) ; v2(3395,2800) 3395,2440 3485,2350 LCD.23@3550,2350
  Bottom Layer w8: v1(2255,3250) 2424,3081 2424,2876 2500,2800 v2(2635,2800) ; v2(3150,2800) v2(3395,2800)
LCD_COM2: LCD.22 U1.65 | length 2421.1
  Top Layer w8: U1.65@1954.13,3264.37 2049.37,3264.37 2060,3275 v1(2235,3275) ; v2(2635,2900) v2(3150,2900) ; v2(3365,2900) 3365,2370 3485,2250 LCD.22@3550,2250
  Bottom Layer w8: v1@2230,3275 v1(2235,3275) 2238.19,3271.81 2264.03,3271.81 2276.81,3259.03 2276.81,3247.99 2438,3086.8 2438,2960 2498,2900 v2(2635,2900) ; v2(3150,2900) v2(3365,2900)
LCD_COM3: LCD.21 U1.66 | length 2515.4
  Top Layer w8: U1.66@1954.13,3284.06 2049.26,3284.06 2062.01,3296.81 v1@2256.81,3296.81 ; v2(2635,3000) v2(3150,3000) ; v2(3335,3000) 3335,2305 3485,2155 3545,2155 LCD.21@3550,2150
  Bottom Layer w8: v1(2260,3300) 2290.81,3269.19 2290.81,3253.79 2452,3092.6 2452,3050 2502,3000 v2(2635,3000) ; v2(3150,3000) v2(3335,3000)
LCD_R03: R11.1 R11.2 R14.2 U1.71 | length 901.8
  Top Layer w8: U1.71@1957.09,3382.48 2068.49,3382.48 2070.01,3384 2144,3384 R14.2@2170,3410 2178,3418 2178,3388 2221.64,3388 2229.64,3396 2235.8,3396 2247.3,3407.5 2286.14,3407.5 2295,3416.36 2295,3570.64 2289.14,3576.5 2263.5,3576.5 R11.1@2130,3710 ; R11.1@2130.79,3712.91 2130.79,3780.79 R11.2@2175,3825
LCD_R13: R13.1 R14.1 U1.72 | length 326.5
  Top Layer w8: U1.72@1957.09,3402.17 1992.52,3402.17 2000.35,3410 2136.36,3410 2158.36,3432 2193,3432 R14.1@2205,3420 ; R14.1@2215,3410 2230,3410 2245,3425 R13.1@2270,3425
LCD_R23: R12.1 R13.2 U1.73 | length 341.8
  Top Layer w8: U1.73@1953.15,3421.85 U1.73@1954.13,3421.85 1992.41,3421.85 1994.55,3424 2130.56,3424 2152.56,3446 2186,3446 R12.1@2210,3470 ; R12.1@2210,3468.62 R13.2@2275,3468.62
LCD_R33: C9.1 R12.2 U1.74 | length 292.7
  Top Layer w8: U1.74@1954.13,3441.54 2121.54,3441.54 2150,3470 R12.2@2170,3470 C9.1@2170,3535
LED1: R23.1 U1.3 | length 1367
  Top Layer w8: U1.3@1346.18,3421.85 1542.95,3421.85 1619,3345.8 1619,3096 1635,3080 v1(1635,3035) v1@1645,3035 ; v2(1800,2550.22) v2@1805.22,2545 ; v2@1805.22,2550 R23.1@1870.47,2550
  Bottom Layer w8: v1(1635,3035) 1620,3020 1620,2615 1620,2565 1635,2550 v2@1800.22,2550
LED2: R24.1 U1.4 | length 1389
  Top Layer w8: U1.4@1346.18,3402.17 1542.83,3402.17 1605,3340 v1(1605,3065) ; v2(1800,2475.22) 1800.22,2475 R24.1@1870.47,2475
  Bottom Layer w8: v1(1605,3065) 1605,2520 1649.78,2475.22 ; 1650,2475 1649.78,2475.22 ; v2(1800,2475.22) 1649.78,2475.22
LED3: R25.1 U1.12 | length 1309.5
  Top Layer w8: U1.12@1346.18,3244.69 1535.31,3244.69 1590,3190 1590,3110 v1(1575,3095) ; v2(1800,2405.22) 1800.22,2405 R25.1@1870.47,2405
  Bottom Layer w8: v1(1575,3095) 1575,3050 1590,3035 1590,2465 1649.78,2405.22 ; 1650,2405 1649.78,2405.22 ; v2(1800,2405.22) 1649.78,2405.22
LFXIN: C18.1 U1.6 Y2.1 | length 333
  Top Layer w8: Y2.1@1050,3450 1090,3450 1177.2,3362.8 U1.6@1345.87,3362.8 U1.6@1346.85,3362.8
LFXOUT: C17.2 U1.7 Y2.2 | length 487.4
  Top Layer w8: C17.2@885,3450 Y2.2@935,3450 ; Y2.2@930,3395 981.89,3343.11 U1.7@1345.87,3343.11
NetC7_1: C7.1 R15.1 Y3.1 | length 258.7
  Top Layer w8: C7.1@1238.74,3874.61 1252.36,3860.98 Y3.1@1252.36,3811.61 ; Y3.1@1261.3,3740.12 1261.3,3668.82 1323.23,3606.89 R15.1@1354.41,3606.89
NetC11_2: C11.2 J8.1 R16.1 | length 262.5
  Top Layer w12: C11.2@1500.39,3884.92 1500.39,4000.59 1551.57,3949.41 R16.1@1551.57,3874.92
NetC12_2: C12.2 J8.7 R17.1 | length 262.5
  Top Layer w12: R17.1@1748.43,3874.92 1748.43,3949.41 1799.61,4000.59 C12.2@1799.61,3884.92
NetC15_1: C15.1 R26.1 Y1.2 | length 173.9
  Top Layer w8: C15.1@1220.71,3299.29 Y1.2@1220.71,3205 1244.17,3205 R26.1@1283.86,3244.69
NetC412_1: C412.1 U402.3 | length 63.4
  Top Layer w12: C412.1@1480,698.62 1488.58,707.2 U402.3@1539.88,707.2
NetD100_1: D100.1 R104.1 | length 56.9
  Top Layer w8: D100.1@290,835.1 R104.1@346.85,835.1
NetD101_1: D101.1 R105.1 | length 56.9
  Top Layer w8: D101.1@290,765.1 R105.1@346.85,765.1
NetD102_1: D102.1 D102.2 Q102.1 R122.1 | length 358.9
  Top Layer w8: R122.1@575,452.87 572.6,450.47 D102.2@572.6,378.74 D102.1@647.4,378.74 647.4,354.09 665,336.5 775,336.5 792.4,353.9 Q102.1@792.4,378.74
NetD102_3: D102.3 Q101.1 Q102.3 R120.2 | length 271.9
  Top Layer w8: D102.3@610,284.25 Q102.3@755,284.25 755,276.5 778.62,252.87 778.62,226.5 780.59,224.53 Q101.1@780.59,167.99
NetD103_3: D103.3 L101.1 Q101.3 | length 537.7
  Top Layer w20: L101.1@480,296.5 417.76,234.25 D103.3@417.76,186.5 417.76,133.74 446.5,105 Q101.3@755,105
NetD201_1: D201.1 R202.1 | length 105.8
  Top Layer w8: R202.1@1680,1605 1680,1640 1705,1665 D201.1@1740.47,1665
NetD202_1: D202.1 R204.1 | length 71.2
  Top Layer w8: R204.1@1681.65,1565 1711.65,1595 D202.1@1740.47,1595
NetD203_1: D203.1 R205.1 | length 56.9
  Top Layer w8: R205.1@1683.62,1525 D203.1@1740.47,1525
NetJ1_2: J1.2 R40.2 | length 135.7
  Top Layer w8: R40.2@1700,1935 1700,2000 J1.2@1750,2050
NetJ1_4: J1.4 R39.2 | length 105
  Top Layer w8: R39.2@1650,1935 J1.4@1650,2040
NetJ1_6: J1.6 R8.2 | length 135.7
  Top Layer w8: J1.6@1550,2050 1600,2000 R8.2@1600,1935
NetJ1_8: J1.8 R7.2 | length 116.4
  Top Layer w8: R7.2@1450,1938.62 J1.8@1450,2050 J1.8@1450,2055
NetJ1_10: J1.10 R6.2 | length 139.2
  Top Layer w8: J1.10@1355,2055 1355,2045 1410,1990 R6.2@1410,1938.62
NetJ3_1: J3.1 R1.2 | length 779.2
  Top Layer w8: v2(605,2005) 620,1990 779.8,1990 802,1967.8 802,1843.4 858.4,1787 958,1787 1000,1745 R1.2@1000,1715
  Bottom Layer w8: J3.1@450,2050 495,2005 v2(605,2005)
NetJ3_3: J3.3 R2.2 | length 659.7
  Top Layer w8: J3.3@550,2050 550,2015 590,1975 775,1975 788,1962 788,1837.6 852.6,1773 932,1773 960,1745 R2.2@960,1715
NetJ3_5: J3.5 R3.2 | length 680.4
  Top Layer w8: v2(825,2010) 820,2005 830,1995 830,1855 870,1815 1010,1815 1080,1745 R3.2@1080,1715
  Bottom Layer w8: J3.5@650,2050 692.48,2007.52 822.52,2007.52 v2(825,2010)
NetJ3_7: J3.7 R4.2 | length 528.2
  Top Layer w8: J3.7@755,2055 755,2035 816,1974 816,1849.2 864.2,1801 984,1801 1040,1745 R4.2@1040,1715
NetJ5_5: J5.5 R28.1 | length 1346.7
  Top Layer w8: v2(3200,1370) R28.1@3200,1410
  Bottom Layer w8: J5.5@2030,1040 2069.92,1040 2112.4,1082.48 2157.44,1082.48 2444.96,1370 v2(3200,1370)
NetJ5_7: J5.7 R29.1 | length 1478.6
  Top Layer w8: v2(3250,1370) R29.1@3250,1410
  Bottom Layer w8: J5.7@2031.76,935 2094.28,997.52 2147.6,997.52 2172.48,1022.4 2172.48,1075.72 2451.76,1355 3178.59,1355 3189.33,1344.25 3210.67,1344.25 3236.41,1370 v2(3250,1370)
NetJ5_9: J5.9 R27.1 | length 1592.9
  Top Layer w8: v2(3300,1370) R27.1@3300,1410
  Bottom Layer w8: J5.9@2030,840 2080,890 2080,950.08 2113.44,983.52 2153.39,983.52 2186.48,1016.61 2186.48,1057.92 2463.56,1335 3178.79,1335 3183.54,1330.25 3246.67,1330.25 3286.41,1370 v2(3300,1370)
NetJ5_13: J5.13 R33.2 | length 1575.6
  Top Layer w8: v2@3050,1305 R33.2@3050,1410
  Bottom Layer w8: J5.13@2030,640 2069.92,640 2127.44,697.52 2147.6,697.52 2172.48,722.4 2172.48,722.48 2200.48,750.48 2200.48,1052.12 2454.36,1306 v2(3048,1306)
NetJ5_15: J5.15 R38.2 | length 1053.4
  Top Layer w8: J5.15@2020,540 2077.52,597.52 2147.6,597.52 2172.48,622.4 2172.48,976.3 2356.81,1160.63 2356.81,1403.19 R38.2@2350,1410
NetJ5_17: J5.17 R50.2 | length 1217.8
  Top Layer w8: J5.17@2025,440 1955,510 1955,1280 2085,1410 R50.2@2250,1410
NetJ5_19: J5.19 R51.2 | length 1408.3
  Top Layer w8: J5.19@2030,340 2072.48,382.48 2072.48,457.6 2047.6,482.48 2002.52,482.48 1969,516 1969,1274.2 2087.3,1392.5 2266.14,1392.5 2283.64,1410 R51.2@2300,1410
NetJ6_4: J6.4 R37.2 | length 1541.8
  Top Layer w8: R37.2@2400,1410 2627.52,1182.48 3787.52,1182.48 J6.4@3830,1140
NetJ6_6: J6.6 R32.1 | length 1228.3
  Top Layer w8: R32.1@3000,1410 3000,1315 3034.75,1280.25 3058.67,1280.25 3060.89,1282.48 3847.6,1282.48 3872.48,1257.6 3872.48,1082.48 J6.6@3830,1040
NetJ6_12: J6.12 R34.1 | length 1470.6
  Top Layer w8: R34.1@3100,1410 3125.16,1410 3128,1407.16 3128,1385.79 3183.54,1330.25 3885.95,1330.25 3917,1299.2 3917,827 J6.12@3830,740
NetJ6_14: J6.14 R35.1 | length 1546.8
  Top Layer w8: R35.1@3150,1410 3174.25,1385.75 3174.25,1359.33 3189.33,1344.25 3891.75,1344.25 3931,1305 3931,741 J6.14@3830,640
NetJ6_16: J6.16 R36.2 | length 2427.1
  Top Layer w8: R36.2@2450,1410 2866.36,1410 2883.86,1427.5 3927.5,1427.5 3945,1410 3945,655 J6.16@3830,540
NetJ6_18: J6.18 R31.1 | length 1419.1
  Top Layer w8: R31.1@2900,1410 2900,1275 2910,1265 v2@2910,1255
  Bottom Layer w8: v2@2908,1241.92 v2(2908,1246) 3669,485 3785,485 J6.18@3830,440
NetJ6_20: J6.20 R30.1 | length 1592.2
  Top Layer w8: R30.1@2950,1410 2950,1275 v2@2980,1245
  Bottom Layer w8: v2(2978,1246) 3641.52,582.48 3847.6,582.48 3872.48,557.6 3872.48,382.48 J6.20@3830,340
NetL3_1: L3.1 U3.2 | length 122.6
  Top Layer w10: U3.2@692.4,3930.47 L3.1@815,3930.47
NetLED1_1: LED1.1 R23.2 | length 35.5
  Top Layer w8: R23.2@1915,2550 LED1.1@1950.47,2550
NetLED2_1: LED2.1 R24.2 | length 35
  Top Layer w8: R24.2@1915,2475 LED2.1@1950,2475
NetLED3_1: LED3.1 R25.2 | length 40
  Top Layer w8: R25.2@1915,2405 1950.47,2405 LED3.1@1955,2405
NetQ102_2: Q102.2 R124.1 | length 167.9
  Top Layer w8: Q102.2@717.6,378.74 717.6,507.6 730,520 R124.1@730,541.5
NetQ400_3: Q400.3 R406.1 | length 96.4
  Top Layer w8: Q400.3@1050.95,270 1050.95,330.94 1066.38,346.38 R406.1@1066.38,360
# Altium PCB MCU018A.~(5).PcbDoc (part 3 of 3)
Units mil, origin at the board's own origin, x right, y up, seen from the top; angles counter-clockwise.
Board outline 4035 x 4400 mil, 2 copper layers (Top Layer, Bottom Layer), stack 62 mil thick; 269 components, 230 nets, 958 pads, 568 vias.

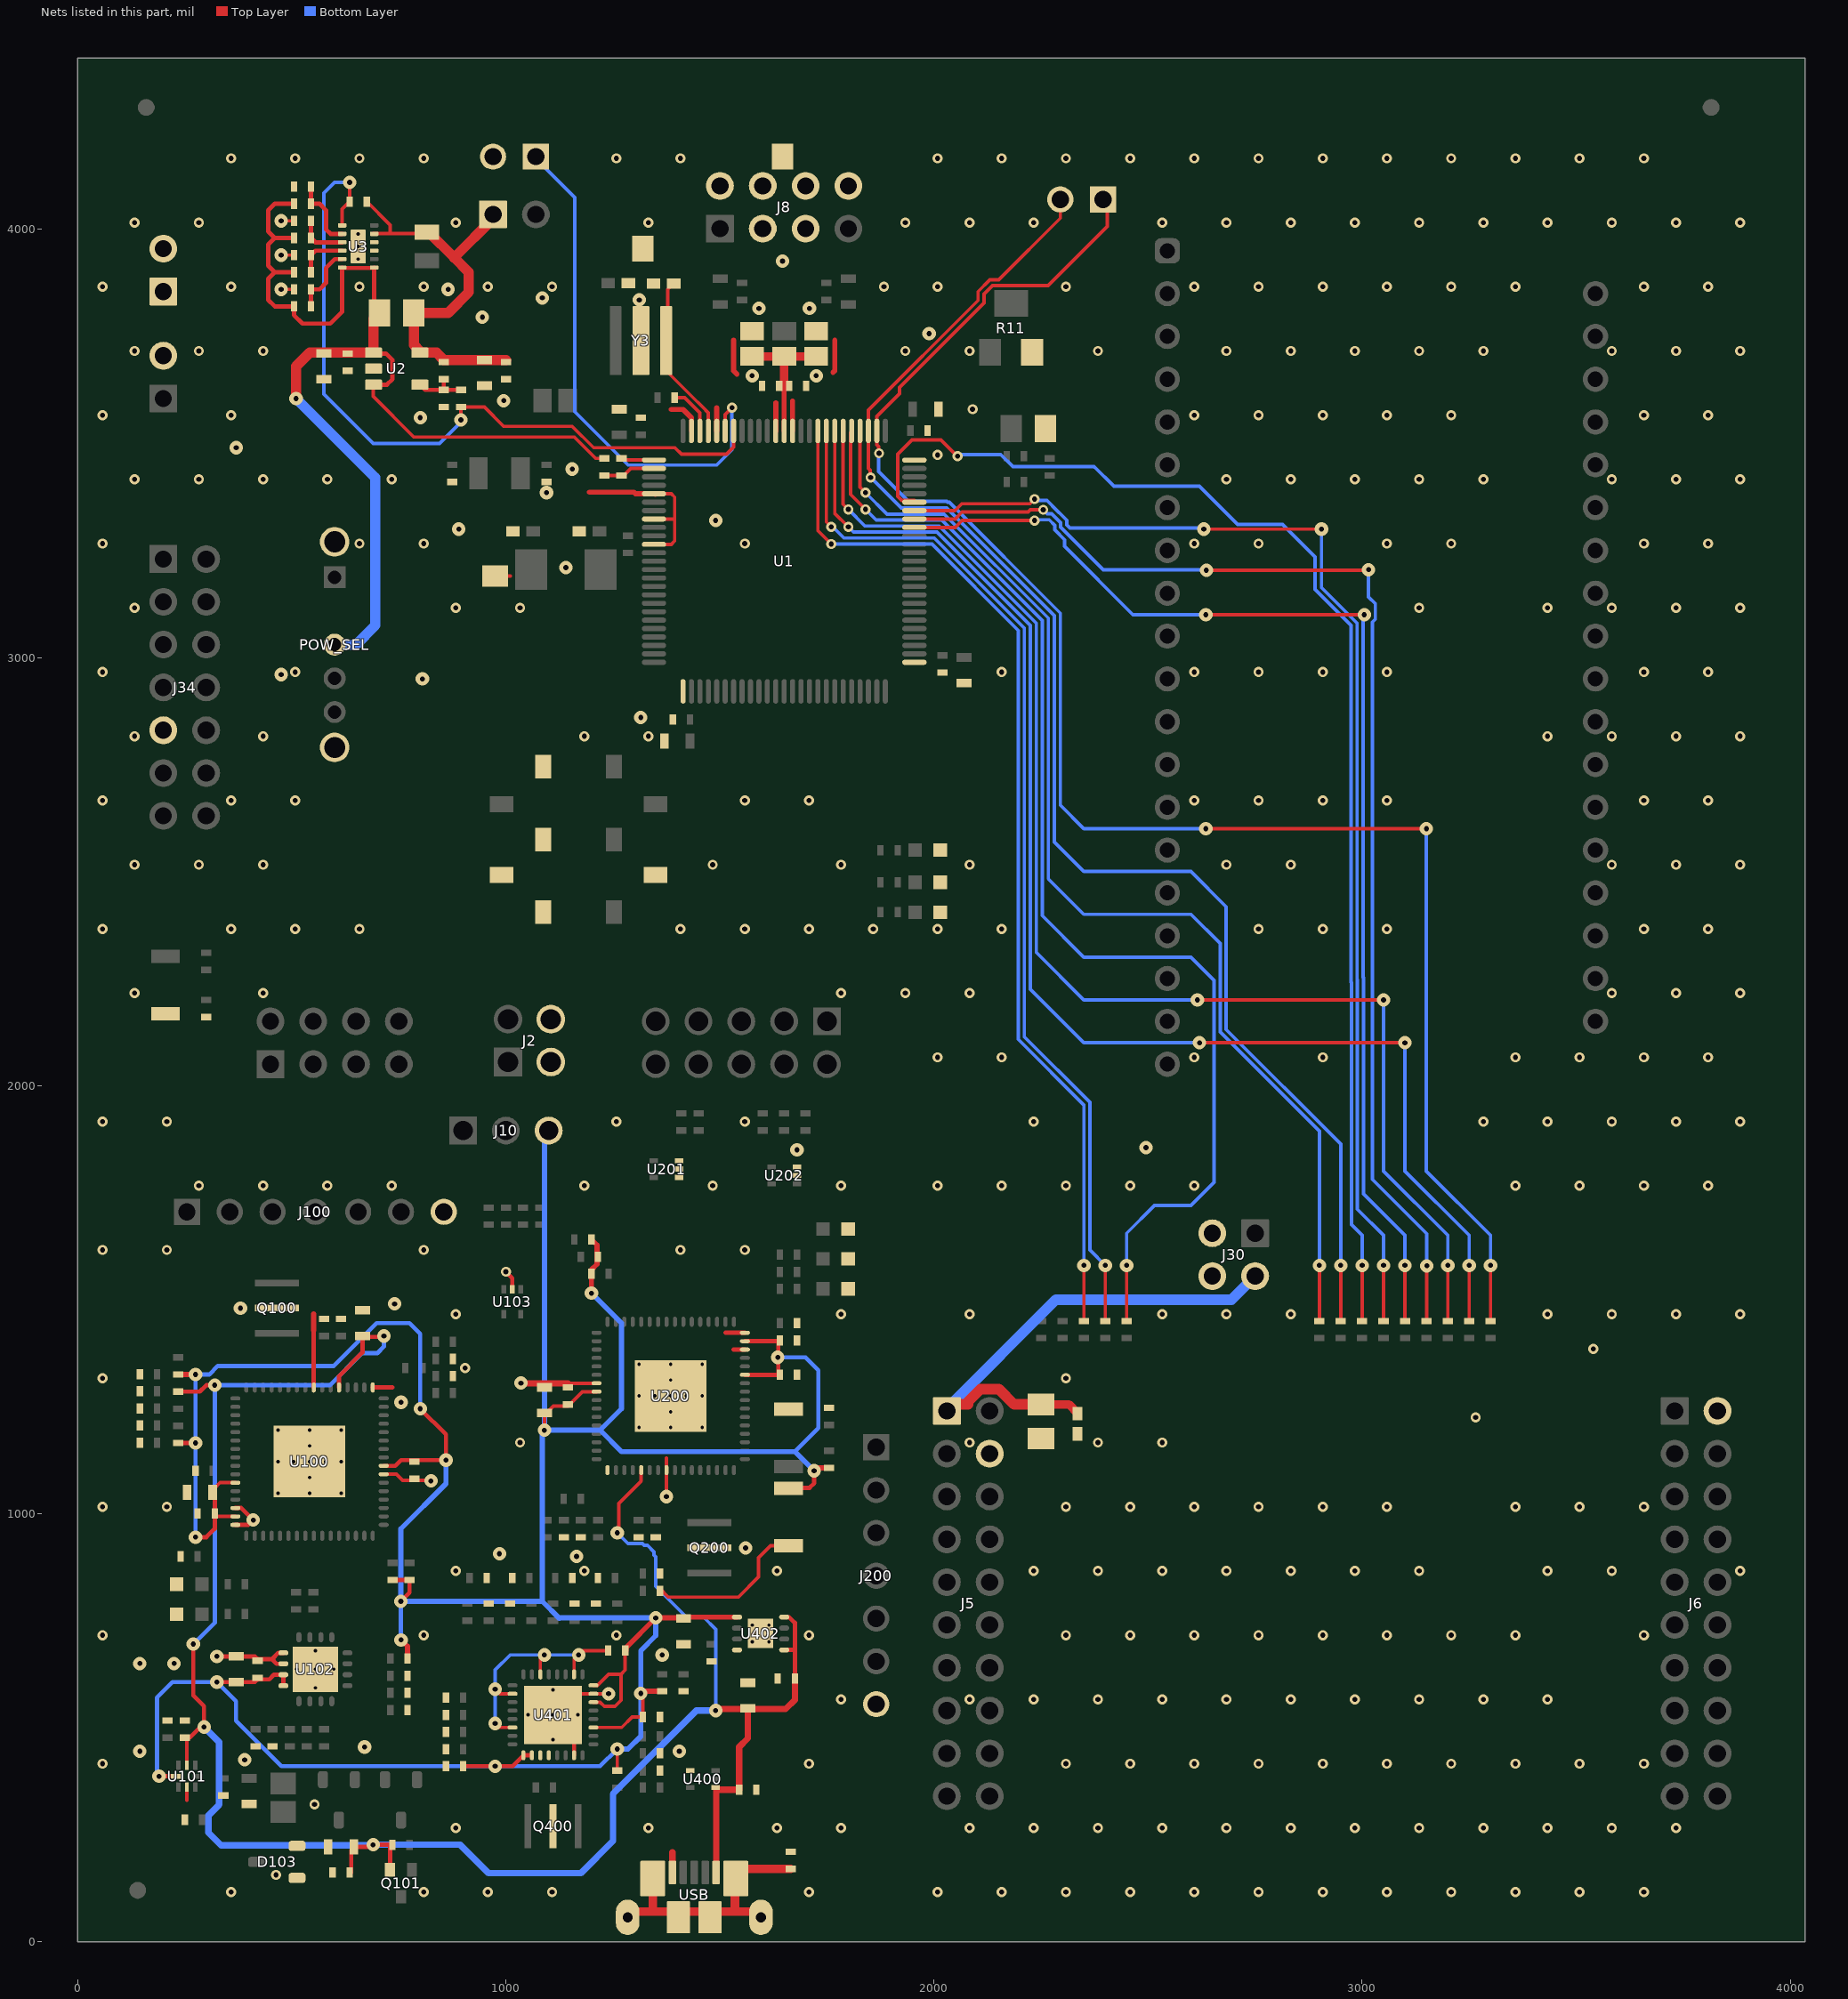
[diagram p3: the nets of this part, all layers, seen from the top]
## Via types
v1: diameter 23.62, hole 11.81, Top Layer to Bottom Layer, tented both sides, 344 vias
v2: diameter 31.5, hole 11.81, Top Layer to Bottom Layer, tented both sides, 181 vias
v3: diameter 19.68, hole 7.87, Top Layer to Bottom Layer, tented both sides, 35 vias
v4: diameter 19.68, hole 7.87, Top Layer to Bottom Layer, 8 vias

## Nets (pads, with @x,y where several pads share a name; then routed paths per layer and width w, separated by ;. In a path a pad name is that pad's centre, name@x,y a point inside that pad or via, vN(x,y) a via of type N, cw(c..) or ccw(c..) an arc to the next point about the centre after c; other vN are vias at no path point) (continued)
NetR20_1: R20.1 R21.2 R22.2 U2.4 | length 126
  Top Layer w10: U2.4@799.13,3637.28 811.42,3625 R21.2@855,3625 ; R20.1@855,3650 R21.2@855,3625 ; R22.2@895,3625 R21.2@855,3625
NetR41_1: R41.1 R42.1 U3.11 | length 162.3
  Top Layer w10: R41.1@545,3820 R42.1@545,3860 565,3860 580,3875 580,3910 600.47,3930.47 U3.11@617.6,3930.47
NetR43_1: R43.1 R44.1 U3.10 | length 116.8
  Top Layer w10: R43.1@545,3900 R44.1@545,3940 555.16,3950.16 U3.10@617.6,3950.16
NetR45_1: R45.1 R46.1 U3.9 | length 116.8
  Top Layer w10: R46.1@545,4020 R45.1@545,3980 555.16,3969.84 U3.9@617.6,3969.84
NetR47_1: R47.1 R48.1 U3.8 | length 168.1
  Top Layer w10: R48.1@545,4100 R47.1@545,4060 565,4060 580,4045 580,4000 590.47,3989.53 U3.8@617.6,3989.53
NetR211_2: R211.2 S202.1 | length 386.6
  Top Layer w8: R211.2@1358.3,826.1 1379.39,805 1543.07,805 1590,851.93 1590,897.05 1618.07,925.12 S202.1@1660,925.12
NetR418_1: R418.1 U401.10 U401.14 U401.18 U401.22 | length 592.5
  Top Layer w8: v2(975,510) 984.53,500.47 U401.22@1015.51,500.47 ; v2(975,590) 985.79,579.21 U401.18@1015.51,579.21 ; U401.14@1080.47,624.49 1080.47,660.47 v2(1090,670) ; U401.10@1159.21,624.49 1159.21,659.21 v2(1170,670) 1180,680 R418.1@1235,680
  Bottom Layer w8: v2(975,510) v2(975,590) 975,635 1010,670 v2(1090,670) v2(1170,670)
PVDD: C3.2 C4.1 C23.1 C24.2 L2.1 U1.88 | length 323.9
  Top Layer w12: U1.88@1650,3529.13 1650,3630.51
  Top Layer w20: C23.1@1575.2,3703.35 L2.1@1650.32,3703.35 ; 1650,3630.51 1650,3703.03 L2.1@1650.32,3703.35 ; C24.2@1724.8,3703.35 L2.1@1650.32,3703.35
RF_CTS: J4.1 R27.2 U1.77 | length 4045.3
  Top Layer w8: 1870.31,3567.68 1919.25,3616.61 1919.25,3630.67 2116.79,3828.2 2116.79,3848.88 2136.49,3868.58 2266.43,3868.58 2404.81,4006.97 2404.81,4029.81 2405,4030 J4.1@2405,4070 ; v1@1870.47,3476.97 1870.47,3492.72 1866.54,3496.65 U1.77@1866.54,3529.13 1866.54,3563.58 1874.41,3571.46 ; v2(2635,2600) v2(3150,2600) ; R27.2@3300,1453.62 v2(3300,1580)
  Bottom Layer w8: v1@1870.47,3476.97 1870.47,3434.53 1940,3365 2030,3365 2032,3363 2035.59,3363 2295,3103.59 2295,2655 2350,2600 v2(2635,2600) ; v2(3150,2600) 3145,2600 3150,2595 3150,1800 3300,1650 v2(3300,1580)
  other v1: 1871.54,3476.97
RF_GND: C21.2 C28.2 J5.4 J6.2 J30.4
  other v1: 2008,116 2158,116 2308,116 2458,116 2608,116 2758,116 2908,116 3058,116 3208,116 3358,116 3508,116 3658,116 2083,266 2233,266 2383,266 2533,266 2683,266 2833,266 2983,266 3133,266 3283,266 3433,266 3583,266 3733,266 2308,416 2458,416 2608,416 2758,416 2908,416 3058,416 3208,416 3358,416 3508,416 3658,416 2083,566 2233,566 2383,566 2533,566 2683,566 2833,566 2983,566 3133,566 3283,566 3433,566 2308,716 2458,716 2608,716 2758,716 2908,716 3058,716 3208,716 3358,716 3658,716 2233,866 2383,866 2533,866 2683,866 2833,866 2983,866 3133,866 3433,866 3583,866 3883,866 2308,1016 2458,1016 2608,1016 2758,1016 2908,1016 3058,1016 3358,1016 3508,1016 3658,1016 2083,1166 2383,1166 2533,1166 3265,1225 2308,1316 3540,1385 2083,1466 2533,1466 2683,1466 2833,1466 3433,1466 3583,1466 3733,1466 3883,1466
RF_GPIO0: R31.2 U1.79 | length 2743.5
  Top Layer w8: U1.79@1827.17,3529.13 1827.17,3397.83 1834.82,3390.18 v1(1840,3385) ; R31.2@2900,1455 v2(2900,1580)
  Bottom Layer w8: v1(1840,3385) 1890,3335 2023.99,3335 2267,3091.99 2267,2483 2350,2400 2600,2400 2668.33,2331.67 2668.33,2125 2900,1893.33 v2(2900,1580)
RF_GPIO2: J4.2 R30.2 U1.78 | length 3493.3
  Top Layer w8: v1@1850.79,3421.85 1850.79,3437.6 1846.85,3441.54 U1.78@1846.85,3529.13 1846.85,3578.06 2102.79,3834 2102.79,3854.68 2130.69,3882.58 2151.37,3882.58 2295,4026.21 J4.2@2295,4070 J4.2@2295,4080 ; R30.2@2950,1450 v2(2950,1580)
  Bottom Layer w8: v1@1850.79,3421.85 1923.64,3349 2029.79,3349 2281,3097.79 2281,2569 2350,2500 2600,2500 2682.33,2417.67 2682.33,2130.8 2950,1863.13 v2(2950,1580)
  other v1: 1851.85,3420.47
RF_GPIO5: R37.1 U1.83 | length 2471.2
  Top Layer w8: U1.83@1748.43,3529.13 1748.43,3316.57 v1(1760,3305) ; R37.1@2400,1453.62 v2(2400,1580)
  Bottom Layer w8: v1(1760,3305) 1763.59,3305 1789.59,3279 2000.8,3279 2211,3068.8 2211,2113.8 2364,1960.8 2364,1616 v2(2400,1580)
RF_RESET: R36.1 U1.80 | length 2793.8
  Top Layer w8: U1.80@1805,3525 1805,3380.94 v1(1840,3345.94) ; R36.1@2450,1453.62 v2(2450,1580)
  Bottom Layer w8: v1(1840,3345.94) 1864.94,3321 2018.2,3321 2253,3086.2 2253,2397 2350,2300 2600,2300 2654.33,2245.67 2654.33,1774.33 2600,1720 2515,1720 2450,1655 v2(2450,1580)
RF_RTS: R38.1 U1.84 | length 2470.5
  Top Layer w8: U1.84@1728.74,3529.13 1728.74,3296.26 v1(1760,3265) ; R38.1@2350,1453.62 v2(2350,1580)
  Bottom Layer w8: v1(1760,3265) 1995,3265 2197,3063 2197,2108 2350,1955 v2(2350,1580)
RF_RXD: R28.2 U1.81 | length 3170.7
  Top Layer w8: U1.81@1787.8,3529.13 1787.8,3358.15 v1(1800,3345.94) ; v2(2615,2200) v2(3050,2200) ; R28.2@3200,1455 v2(3200,1580)
  Bottom Layer w8: v1(1800,3345.94) 1838.94,3307 2012.4,3307 2239,3080.4 2239,2311 2350,2200 v2(2615,2200) ; v2(3050,2200) 3050,1800 3200,1650 v2(3200,1580)
RF_SPI_CLK: R33.1 U1.69 | length 2900.5
  Top Layer w8: U1.69@1954.13,3343.11 2048.91,3343.11 2065,3359.2 2224.2,3359.2 v1(2235,3370) ; v2(2630,3300) v2(2905,3300) ; R33.1@3050,1453.62 v2(3050,1580)
  Bottom Layer w8: v1(2235,3370) 2238.19,3366.81 2264.03,3366.81 2276.81,3354.03 2276.81,3353.63 2309.81,3320.63 2309.81,3309.99 2317.4,3302.4 v2@2627.6,3302.4 ; v2(2905,3300) 2905,3163.59 2988,3080.59 2988,2247.4 2989,2246.4 2989,1711 3050,1650 v2(3050,1580)
RF_SPI_CSN: R32.2 U1.70 | length 3077.9
  Top Layer w8: U1.70@1954.13,3362.8 1954.13,3366.57 1924.91,3366.57 1915.59,3375.89 1915.59,3474.84 1948.75,3508 1996.64,3508 1997.11,3508.46 2016.14,3508.46 v1@2055.51,3469.09 ; R32.2@3000,1453.62 v2(3000,1580)
  Bottom Layer w8: v1(2055,3470) 2059,3474 2155.8,3474 2184.05,3445.75 2374.05,3445.75 2374.8,3445 2375,3445 2420,3400 2620,3400 2709.33,3310.67 2814.33,3310.67 2890,3235 2890,3158.79 2974,3074.79 2974,2241.6 2975,2240.6 2975,1675 3000,1650 v2(3000,1580)
RF_SPI_MISO: R35.2 U1.68 | length 2948.6
  Top Layer w8: U1.68@1954.13,3323.43 2049.03,3323.43 2065.3,3339.7 2219.7,3339.7 2225,3345 v1(2255,3345) ; v2(2636.06,3203.94) v2@3015,3203.94 ; R35.2@3151.06,1451.06 v2(3151.06,1578.94)
  Bottom Layer w8: v1(2255,3345) 2264.19,3335.81 2274.83,3335.81 2295.81,3314.83 2295.81,3304.19 2395,3205 v2@2635,3205 ; v2(3015,3205) 3015,3141.5 3030.75,3125.75 3030.75,3089.33 3024.25,3082.84 3024.25,1780.75 3151.06,1653.94 v2(3151.06,1578.94)
RF_SPI_MOSI: R34.2 U1.67 | length 2852.7
  Top Layer w8: U1.67@1954.13,3303.74 2049.14,3303.74 2065.4,3320 v1(2235,3320) ; v2(2635,3100) v2(3005,3100) ; R34.2@3100,1453.62 v2(3100,1580)
  Bottom Layer w8: v1(2235,3320) 2236.81,3321.81 2269.03,3321.81 2281.81,3309.03 2281.81,3297.99 2304.81,3274.99 2304.81,3259.59 2464.4,3100 v2(2635,3100) ; v2@3002,3100 3002,2253.2 3003,2252.2 3003,1747 3100,1650 v2(3100,1580)
RF_TXD: R29.2 U1.82 | length 3241.3
  Top Layer w8: U1.82@1768.11,3529.13 1768.11,3336.89 v1(1800,3305) ; v2(2620,2100) v2(3100,2100) ; R29.2@3250,1455 v2(3250,1580)
  Bottom Layer w8: v1(1800,3305) 1812,3293 2006.6,3293 2225,3074.6 2225,2225 2350,2100 v2(2620,2100) ; v2(3100,2100) 3100,1800 3250,1650 v2(3250,1580)
RF_VCC: C21.1 C28.1 J5.1 J30.2 | length 1185.1
  Top Layer w20: C21.1@2250,1255 2315,1255 C28.1@2335,1235
  Top Layer w25: J5.1@2040,1255 2079.02,1255 2079.02,1261.12 2108.88,1290.98 2151.12,1290.98 2187.1,1255 C21.1@2250,1255
  Bottom Layer w25: J5.1@2030,1245 2285,1500 2695,1500 J30.2@2750,1555
SOURCE_VCC: C10.1 C13.1 POW_SEL.2 R9.2 R19.2 R41.2 R43.2 R45.2 R47.2 U2.1 U2.3 U3.1 U3.12 | length 2757.6
  Top Layer w8: U2.3@690.87,3637.28 690,3636.42 690,3610 785,3515 1160,3515 1210,3465 R9.2@1230,3465
  Top Layer w10: R43.2@505,3900 460,3900 ; R45.2@505,3980 460,3980 ; R47.2@505,4060 460,4060 445,4045 445,3995 460,3980 ; U2.3@690.87,3637.28 722.28,3637.28 735,3650 735,3695 720,3710 U2.1@692.95,3710 ; U3.1@692.4,3910.79 U3.1@692.4,3909.63 ; R19.2@705,3805 692.4,3817.6 U3.1@692.4,3909.63 ; 460,3900 445,3915 445,3965 460,3980 ; 460,3900 445,3885 445,3835 460,3820 R41.2@505,3820 505,3800 525,3780 590,3780 617.6,3807.6 U3.12@617.6,3910.79 618.76,3909.63 U3.1@692.4,3909.63
  Top Layer w24: v2(510,3605) 510,3680 542.09,3712.09 U2.1@690.87,3712.09 690.87,3790.87 R19.2@705,3805
  Bottom Layer w24: v2(510,3605) 695,3420 695,3075 650,3030 POW_SEL.2@600,3030
TARGET_GND: BUT_DOWN.1 BUT_LEFT.1 BUT_RIGHT.1 BUT_SELECT.1 BUT_UP.1 C1.2 C2.1 C5.2 C6.2 C9.2 C10.2 C13.2 C14.2 C19.2 C20.2 C22.2 C25.2 C26.2 C27.1 J2.4 J7.2 J30.3 J31.1 J31.2 J33.2 J34.9 LED1.2 LED2.2 LED3.2 MCU_RESET.1 NT1.2 NT2.2 NT3.2 POW_SEL.S1 POW_SEL.S2 R11.3 R21.1 R42.2 R44.2 R46.2 R48.2 U1.26 U1.51 U1.75 U1.99 U2.2 U3.3 U3.4 U3.13@655,3960 | length 175.9
  Top Layer w8: v2(475,3860) R42.2@505,3860 ; v2(475,3940) R44.2@505,3940 ; v2(475,4020) R46.2@505,4020
  Top Layer w12: 1386.22,3579.33 1413.78,3579.33 1433.46,3559.65 U1.99@1433.46,3529.13
  other v1: 2008,1766 2158,1766 2308,1766 2458,1766 2608,1766 3358,1766 3508,1766 3658,1766 3808,1766 2233,1916 3283,1916 3433,1916 3583,1916 3733,1916 3883,1916 2008,2066 2158,2066 2608,2066 2908,2066 3358,2066 3508,2066 3658,2066 3808,2066 133,2216 433,2216 1783,2216 1933,2216 2083,2216 3583,2216 3733,2216 3883,2216 58,2366 358,2366 508,2366 658,2366 1408,2366 1558,2366 1708,2366 1858,2366 2008,2366 2158,2366 2758,2366 2908,2366 3058,2366 3658,2366 3808,2366 133,2516 283,2516 433,2516 1483,2516 1783,2516 2083,2516 2683,2516 2833,2516 3583,2516 3733,2516 3883,2516 58,2666 358,2666 508,2666 1558,2666 1708,2666 2608,2666 2758,2666 2908,2666 3058,2666 3658,2666 3808,2666 133,2816 433,2816 1183,2816 1333,2816 3433,2816 3583,2816 3733,2816 3883,2816 58,2966 508,2966 2158,2966 2608,2966 2758,2966 2908,2966 3058,2966 3658,2966 3808,2966 133,3116 883,3116 1033,3116 3133,3116 3433,3116 3583,3116 3733,3116 3883,3116 58,3266 658,3266 808,3266 1558,3266 2608,3266 2758,3266 3058,3266 3208,3266 3658,3266 3808,3266 133,3416 283,3416 433,3416 583,3416 733,3416 2683,3416 2833,3416 2983,3416 3133,3416 3283,3416 3583,3416 3733,3416 3883,3416 2008.27,3473.03 58,3566 358,3566 2608,3566 2758,3566 2908,3566 3058,3566 3208,3566 3658,3566 3808,3566 2090,3580 133,3716 283,3716 433,3716 1933,3716 2083,3716 2383,3716 2683,3716 2833,3716 2983,3716 3133,3716 3283,3716 3583,3716 3733,3716 3883,3716 58,3866 358,3866 658,3866 808,3866 958,3866 1108,3866 1883,3866 2008,3866 2308,3866 2608,3866 2758,3866 2908,3866 3058,3866 3208,3866 3358,3866 3658,3866 3808,3866 133,4016 283,4016 883,4016 1333,4016 1933,4016 2083,4016 2233,4016 2533,4016 2683,4016 2833,4016 2983,4016 3133,4016 3283,4016 3433,4016 3583,4016 3733,4016 3883,4016 358,4166 508,4166 658,4166 808,4166 1258,4166 1408,4166 2008,4166 2158,4166 2308,4166 2458,4166 2608,4166 2758,4166 2908,4166 3058,4166 3208,4166 3358,4166 3508,4166 3658,4166
  other v2: 2495,1855 1315,2860 805,2950 475,2960 1490,3320 370,3490 800,3560 995,3600 1988.58,3756.5 945,3795 1085,3840 865,3860
  other v4: 655,3930.47 655,3960 655,3989.53
TARGET_VCC: C19.1 C20.1 J32.1 L3.2 R19.1 R20.2 R49.1 U2.5 U3.5 | length 987.4
  Top Layer w8: R49.1@675,4065 730,4010 730,3990 ; U3.5@690,3990 730,3990 ; L3.2@810,3990 730,3990
  Top Layer w24: R19.1@780,3805 R19.1@785,3805 ; U2.5@799.13,3712.09 837.91,3712.09 855,3695 C19.1@950,3695 C20.1@1000,3695 ; U2.5@800,3715 785,3730 R19.1@785,3805 ; L3.2@815,3993.46 819.79,3993.46 879.13,3934.13 ; J32.1@970,4025 879.13,3934.13 ; R19.1@785,3805 865,3805 913.25,3853.25 913.25,3900 879.13,3934.13
USB_GND: C100.2 C101.2 C102.2 C103.2 C104.2 C105.2 C106.2 C107.2 C108.2 C109.2 C110.2 C111.2 C112.2 C113.2 C114.2 C115.2 C116.2 C117.2 C118.2 C119.2 C120.2 C121.2 C200.2 C201.2 C202.2 C203.2 C204.2 C205.2 C206.2 C207.2 C208.2 C210.2 C400.2 C401.2 C402.2 C403.2 C404.2 C405.2 C406.2 C407.2 C408.2 C409.2 C410.2 C411.2 C412.2 C413.2 D100.2 D101.2 D103.1 D103.2 D201.2 D202.2 D203.2 J2.3 J100.7 J200.7 Q100.2 Q200.2 Q400.2 R107.1 R109.1 R117.1 R119.1 R121.1 R123.1 R124.2 R210.1 R400.1 R401.2 R402.2 R403.2 R405.1 R410.1 R411.1 R412.1 RUSB.1 S201.1 U100.14 U100.16 U100.39 U100.49 U100.56 U100.65 U101.6 U102.13 U102.14 U102.17 U103.2 U200.14 U200.16 U200.39 U200.49 U200.56 U200.65 U201.1 U201.2 U201.3 U202.2 U202.3 U400.4 U401.7 U401.27 U401.28 U401.31 U401.33 U402.4 U402.9 USB.5 | length 1278.7
  Top Layer w8: 255,330 U101.6@255,360.91 ; U100.39@714.62,1091.97 744.53,1091.97 758.62,1077.87 823.62,1077.87 v2(825,1076.5) ; v3(1110,530) 1159.21,579.21 U401.7@1204.49,579.21 v2(1240,579.21) v2@1244.21,579.21 ; 1145,1304.53 U200.39@1211.77,1304.53 ; v2(1375,1040) 1375.16,1040 U200.56@1375.16,1101.77 1375.16,1129.84 1375,1130
  Top Layer w10: v2(325,666.5) C112.2@368.5,666.5 ; U100.16@368.17,973.86 398.86,973.86 ; U100.14@368.17,1013.23 381.77,1013.23 v2(410,985) ; C112.2@370,666.5 413.62,666.5 420,660.12 453.62,660.12 ; U102.14@480.2,649.29 464.45,649.29 453.62,660.12 ; U102.13@480.2,674.88 468.39,674.88 453.62,660.12 ; U100.56@551,1294.96 551,1427.71 ; U100.49@689.07,1294.72 734.72,1294.72 ; v1(1000,1565) 1015,1550 U103.2@1015,1524.53 ; U401.31@1159.21,435.51 U401.33@1159.21,484.21 ; 1512.64,1422.64 U200.16@1558.23,1422.64 ; 1531.73,1383.27 U200.14@1558.23,1383.27
  Top Layer w12: 551,1427.71 551.24,1427.95 551.24,1466.24
  Top Layer w15: v2(1035,1305) 1044.06,1305 1044.53,1304.53 1145,1304.53 ; USB.5@1388.82,161.81 1388.82,208.82
  other v1: 358,116 808,116 958,116 1108,116 1708,116 463,156 883,266 1333,266 1633,266 1783,266 553,321 58,416 1708,416 1783,566 58,716 808,716 1258,716 1708,716 883,866 1183,866 1633,866 58,1016 208,1016 1033,1166 58,1316 905,1340 883,1466 1783,1466 58,1616 208,1616 808,1616 1408,1616 1558,1616 283,1766 433,1766 583,1766 733,1766 1183,1766 1483,1766 1783,1766 58,1916 208,1916 1258,1916 1558,1916
  other v2: 390,425 145,445 1405,445 670,455 145,650 225,650 1365,670 1165,900 985,906.5 1560,920 755,1260 380,1480 740,1490 1680,1850
  other v3: 1110,471.93 1051.93,530 1168.07,530 1110,588.07 1575.32,700.31 1614.69,700.31 1575.32,739.68 1614.69,739.68 467.58,1047.68 541.39,1047.68 615.21,1047.68 541.39,1084.59 467.58,1121.5 504.49,1121.5 541.39,1121.5 578.3,1121.5 615.21,1121.5 541.39,1158.41 467.58,1195.31 541.39,1195.31 615.21,1195.31 1311.18,1201.18 1385,1201.18 1458.82,1201.18 1385,1238.09 1311.18,1275 1348.09,1275 1385,1275 1421.91,1275 1458.82,1275 1385,1311.91 1311.18,1348.82 1385,1348.82 1458.82,1348.82
  other v4: 555,593.19 511.69,636.5 555,636.5 598.31,636.5 555,679.8
USB_LDO: C102.1 C103.1 C104.1 C112.1 C113.1 C202.1 C203.1 C204.1 C205.1 C408.1 C409.1 C413.1 J10.3 R106.2 R108.2 R111.1 R112.1 R118.1 R200.2 R207.2 R208.2 R209.2 R404.2 R408.2 R418.2 S202.2 U100.11 U100.15 U100.40 U101.4 U102.15 U102.16 U200.11 U200.15 U200.40 U401.3 U401.6 U401.8 U401.25 U401.26 U402.1 | length 9163.7
  Top Layer w8: C102.1@320,993.54 U100.15@368.17,993.54 ; C103.1@320,1060 332.28,1072.28 U100.11@368.17,1072.28 ; v2(1090,1195) 1090,1230 1111.38,1251.38 1145,1251.38 1178.46,1284.84 U200.40@1211.77,1284.84 ; U401.3@1204.49,500.47 1270.47,500.47 1295,525 C409.1@1320,525 1320,580 v2(1315,580) ; U401.6@1204.49,559.53 1220.47,559.53 1230,550 1255,550 1269,564 1269,625 ; U401.8@1204.49,598.9 1213.9,598.9 1240,625 1269,625 ; R408.2@1260,403.62 v2(1260,450) ; R418.2@1278.62,680 1278.62,634.62 1269,625
  Top Layer w10: v2(190,386.5) U101.4@229.41,386.5 ; R108.2@242.63,1165 v2(275,1165) ; v2(275,945) 300.3,945 320,964.7 320,993.54 C102.1@320,1000 C103.1@320,1060 ; v2(325,606.5) C112.1@370,606.5 413.62,606.5 420,612.87 447.13,612.87 457.95,623.7 U102.15@480.2,623.7 ; U102.16@480.2,598.11 U102.15@480.2,619.8 ; U100.40@714.62,1111.65 741.65,1111.65 755.12,1125.12 824.88,1125.12 825,1125 v2(860,1125) 860,1185 v2(800,1245) ; R112.1@735,845 R111.1@775,845 ; v2@755,795.5 775,815.5 R111.1@775,841.38 ; C408.1@903.62,410 1007.5,410 ; v2(975,410) 1015.59,410 U401.25@1041.1,435.51 U401.26@1060.79,435.51 ; U200.11@1558.23,1324.21 1635.59,1324.21 1636.38,1325 1636.38,1405 1634.33,1402.95 U200.15@1558.23,1402.95 ; S202.2@1660,1058.98 1661.32,1060.3 1709.36,1060.3 1720,1070.94 v2(1720,1100)
  Top Layer w12: R106.2@235,1325 v2(275,1325) ; v2(755,705) 770,690 R118.1@770,661.5 ; v2(1200,1515) R207.2@1200,1560 1200,1570 1212.72,1582.72 1212.72,1627.28 R200.2@1200,1640 ; R418.2@1280.26,680 1280.26,686.75 v2(1350,756.5) 1415,756.5 1416.89,758.39 U402.1@1539.88,758.39 ; v2(1315,580) 1315,585 R404.2@1365,585 ; v2(1720,1100) 1727.05,1107.05 R209.2@1755,1107.05
  Bottom Layer w10: v2(190,386.5) 185,391.5 185,570 221.5,606.5 v2(325,606.5) 369.5,561.99 369.5,516.36 475.86,410 v2(975,410) 1220,410 v2(1260,450) ; v2(275,945) v2(275,1165) v2(275,1325) 307.17,1325 327.17,1345 598.31,1345 698.31,1445 775,1445 800,1420 v2(800,1245) ; v2(754.5,795) 754.5,705.5 v2(755,705) ; v2(1635,1365) 1700,1365 1730,1335 1730,1200 1675,1145
  Bottom Layer w12: v2(860,1125) 860,1070 754.5,964.5 v2(754.5,795) 1085,795 ; J10.3@1100,1895 1090,1885 v2(1090,1195) ; v2(1200,1515) 1270,1445 1270,1245 1220,1195 ; v2(1260,450) 1285,450 1315,480 v2(1315,580) 1315,680 1350,715 v2(1350,756.5) 1126.5,756.5 1125,755 1085,795 ; v2(1720,1100) 1675,1145 1270,1145 1220,1195 ; 1085,795 1085,1190 v2(1090,1195) ; v2(1090,1195) 1220,1195
USB_SHIELD: RUSB.2 USB.6 USB.7 USB.8 USB.9 USB.10 USB.11 | length 575.5
  Top Layer w20: USB.7@1278.58,70 1343.05,70 1535,70 ; 1343.05,75 USB.6@1343.05,152.64 ; USB.11@1535,135 1535,70 ; USB.11@1555,170 RUSB.2@1665,170 ; USB.10@1601.42,70 1535,70
USB_VBUS: C116.1 C117.1 C118.1 C119.1 C402.1 C410.1 C411.1 Q101.2 R110.2 R120.1 U100.53 U101.2 U200.53 U400.1 U402.5 U402.8 USB.1 | length 5212.1
  Top Layer w8: U101.2@255,412.09 C119.1@255,475 ; v2(1260,955) 1263.5,958.5 1263.5,1023.5 1316.09,1076.09 U200.53@1316.09,1101.77
  Top Layer w10: R110.2@235,1285 285,1285 300,1300 v2(320,1300) ; C119.1@250,476.5 261.5,476.5 286.5,501.5 v2(295,501.5) 295,550 269.94,575.06 v2(269.94,695.5) ; U100.53@610.31,1294.72 610.31,1321.45 665,1376.14 665,1412.99 715,1412.99 v2(715,1415) ; C118.1@638.62,161.5 638.62,213.62 646.5,221.5 685,221.5 v2(690,226.5) 731.38,226.5 729.41,224.53 Q101.2@729.41,167.99 ; v2(1490,540) v2@1493.5,543.5 ; U402.5@1650.12,681.61 1673.39,681.61 1675,680 ; U402.8@1650.12,758.39 1661.61,758.39 1675,745 1675,680 ; C411.1@1675,611.38 C411.1@1675,615 1675,680
  Top Layer w15: USB.1@1491.18,185.51 1491.18,355 C402.1@1545,355 1545,455 1565,475 C410.1@1565,543.5 ; v2@1493.5,543.5 C410.1@1565,543.5 ; C411.1@1675,611.38 1675,565 1653.5,543.5 C410.1@1565,543.5
  Bottom Layer w8: v2(1260,955) 1285,930 1319.06,930 1323.32,925.75 1330.67,925.75 1345.75,910.67 1345.75,903.32 1350,899.06 1350,830 1421.61,758.39 1461.61,758.39 1490,730 v2(1490,540)
  Bottom Layer w10: v2(269.94,695.5) v2@270.22,695.22 ; v2@688.5,225 v2(690,226.5) ; v2(715,1415) 715,1390 700,1375 663.86,1375 588.86,1300 v2(320,1300) 320,745 v2@270.22,695.22 ; v2@270.22,695.22 270,695 275,690 275,690.43 v2@270.22,695.22
  Bottom Layer w15: v2(295,501.5) 330,466.5 330,320 305,295 305,255 335,225 v2@688.5,225 ; v2(690,226.5) 893.5,226.5 960,160 1175,160 1250,235 1250,345 1445,540 v2(1490,540)
USS_GND: C3.1 C4.2 C23.2 C24.1 J8.2 J8.3 J8.4 J8.5 J8.6 J8.8 NT2.1 U1.87 U1.89 | length 294.3
  Top Layer w12: 1531.89,3740.75 1531.89,3669.88 1539.76,3662.01 ; U1.89@1630.31,3529.13 1630.31,3595.08 ; U1.87@1669.68,3529.13 1669.68,3599.02 ; 1764.17,3665.94 1768.11,3669.88 1768.11,3740.75
  other v2: 1575.2,3658.07 1724.8,3658.07 1590.94,3815.55 1709.06,3815.55 1646.06,3925.79
USSXIN: C8.1 U1.97 Y3.3 | length 253.1
  Top Layer w8: Y3.3@1374.41,3669.88 1425.29,3619 1425.41,3619 1467.15,3577.26 1467.15,3577.14 1472.83,3571.46 U1.97@1472.83,3529.13 ; Y3.3@1378.35,3807.68 1378.35,3859.92 C8.1@1391.97,3873.54
USSXOUT: R15.2 U1.98 | length 116.1
  Top Layer w8: R15.2@1394.09,3606.89 R15.2@1394.41,3606.89 1417.6,3606.89 1419.49,3605 1419.61,3605 1453.15,3571.46 U1.98@1453.15,3529.13
USSXT_BOUT: J7.1 U1.95 | length 1228.1
  Top Layer w8: U1.95@1512.2,3529.13 1512.2,3567.52 v1(1527.95,3583.27)
  Bottom Layer w8: J7.1@1065,4170 1160.75,4074.25 1160.75,3574.25 1285.59,3449.41 1492.52,3449.41 1527.95,3484.84 v1(1527.95,3583.27)
USSXTAL_GND: C7.2 C8.2 NT1.1 U1.96 Y3.2 | length 54.1
  Top Layer w12: U1.96@1492.52,3529.13 1492.52,3583.27
  other v2: 1311.42,3835.24
VCC_SENSE: R9.1 R10.2 U1.2 | length 123
  Top Layer w8: R9.1@1230,3425 R10.2@1270,3425 1275,3425 1291.54,3441.54 U1.2@1345.87,3441.54 U1.2@1346.18,3441.54
VCC_SENSE_EN: R10.1 U1.1 | length 77.7
  Top Layer w8: R10.1@1270,3465 1273.78,3461.22 U1.1@1345.87,3461.22 U1.1@1346.18,3461.22
VSET: R22.1 R49.2 U1.94 U3.7 | length 1798.4
  Top Layer w8: U3.7@617.6,4009.21 617.6,4047.6 R49.2@635,4065 v2(635,4110) ; v2(895,3555) R22.1@895,3585 950,3585 995,3540 1155,3540 1205,3490 1395,3490 1410,3475 1515,3475 1531.89,3491.89 U1.94@1531.89,3529.13
  Bottom Layer w8: v2(635,4110) 600,4110 575,4085 575,3615 690,3500 845,3500 895,3550 v2(895,3555)
XTAL_GND: C15.2 C16.2 C17.1 C18.2 NT3.1 U1.5 U1.8 U1.11 | length 412
  Top Layer w8: NT3.1@985,3190 NT3.1@990,3190 1010,3190 ; U1.5@1345.87,3382.48 U1.5@1349.65,3378.7 ; U1.8@1346.85,3324.41 U1.8@1345.87,3323.43 1390.16,3323.43 ; U1.5@1350.79,3382.48 1386.22,3382.48 1394.09,3374.61 1394.09,3319.49 1394.09,3272.24 1386.22,3264.37 U1.11@1362.6,3264.37
  Top Layer w12: 1195,3386 1299.03,3386 1302.55,3382.48 U1.5@1345.87,3382.48
  other v2: 1140,3210 890,3300 1095,3385 1155,3440
pads on no net: FID1.1 FID2.1 FID3.1 H1.0 H2.0 H3.0 H4.0 J5.2 J5.3 J5.6 J5.8 J5.10 J5.11 J5.12 J5.14 J5.16 J5.18 J5.20 J6.1 J6.3 J6.5 J6.7 J6.8 J6.9 J6.10 J6.11 J6.13 J6.15 J6.17 J6.19 J34.6 J34.10 J34.13 LCD.25 LCD.26 LCD.27 LCD.28 LCD.29 LCD.30 LCD.31 SH-10.0 SH-J1.0 SH-J2.0 SH-J3.0 SH-J4.0 SH-J5.0 SH-J6.0 SH-J7.0 SH-J8.0 SH-J9.0 SH-J11.0 U1.28 U1.92 U1.93 U3.6 U3.13@655,3938.35 U3.13@655,3981.65 U100.3 U100.4 U100.10 U100.12 U100.13 U100.18 U100.19 U100.22 U100.23 U100.24 U100.25 U100.29 U100.30 U100.31 U100.32 U100.33 U100.36 U100.41 U100.42 U100.45 U100.46 U100.47 U100.48 U200.1 U200.2 U200.3 U200.4 U200.5 U200.6 U200.7 U200.8 U200.9 U200.10 U200.12 U200.13 U200.18 U200.19 U200.20 U200.21 U200.22 U200.23 U200.24 U200.28 U200.29 U200.30 U200.31 U200.33 U200.36 U200.41 U200.42 U200.43 U200.44 U200.45 U200.46 U200.47 U200.48 U400.2 U401.5 U401.9 U401.13 U401.17 U401.21 U401.32 U402.2 U402.6 U402.7 USB.4

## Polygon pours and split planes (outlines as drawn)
USB_GND on Bottom Layer "EZFET_GND_BOTTOM" (solid, remove dead copper, pour order 30): 1905,2095 0,2095 0,0 1905,0
TARGET_GND on Bottom Layer "TARGET_GND_BOTTOM" (solid, remove dead copper, pour order 42): 0,4400 0,2125 1950,2125 1950,1625 2800,1625 3995,1625 3995,4400
RF_GND on Bottom Layer "RF_GND_BOTTOM" (solid, remove dead copper, pour order 38): 1950,1585 1950,0 3995,0 3995,1585
XTAL_GND on Bottom Layer "XTAL_GND_BOT" (solid, remove dead copper, pour order 22): 1381.02,3390 1210,3390 1200,3400 1200,3435 1150,3485 890,3485 845,3440 845,3265 885,3230 980,3230 980,3145 1255,3145 1307.8,3197.8 1307.8,3255 1375,3255 1381.02,3261.02
USS_GND on Bottom Layer "USS_GND_BOT" (solid, remove dead copper, pour order 6): 1580,3490 1580,3560 1510,3560 1510,3585 1445,3650 1445,3815 1445,4155 1855,4155 1855,3650 1790,3585 1790,3560 1720,3560 1720,3490
USSXTAL_GND on Bottom Layer "USSXTAL_GND_BOT" (solid, remove dead copper, pour order 14): 1499.92,3495.08 1499.96,3590.04 1440,3650 1440,3910 1400,3950 1245,3950 1200.63,3905.63 1200.63,3634.37 1235,3600 1300,3600 1315,3585 1388.58,3585 1425,3554.19 1425,3495.08
TARGET_GND on Top Layer "TARGET_GND_TOP" (solid, remove dead copper, pour order 40): 0,4400 0,2125 1950,2125 1950,1625 2800,1625 3995,1625 3995,4400 995,4400
USB_GND on Top Layer "EZFET_GND_TOP" (solid, remove dead copper, pour order 28): 1904.45,2095 0,2095 0,0 1904.45,0
USSXTAL_GND on Top Layer "USSXTAL_GND_TOP" (solid, remove dead copper, pour order 10): 1499.92,3495.08 1499.96,3585.85 1440,3645.82 1440,3910 1400,3950 1245,3950 1200.63,3905.63 1200.63,3634.37 1235,3600 1300,3600 1315,3585 1388.58,3585 1425,3554.19 1425,3495.08
XTAL_GND on Top Layer "XTAL_GND_TOP" (solid, remove dead copper, pour order 20): 1381.02,3390 1210,3390 1200,3400 1200,3435 1150,3485 890,3485 845,3440 845,3265 885,3230 980,3230 980,3145 1255,3145 1307.8,3197.8 1307.8,3255 1375,3255 1381.02,3261.02
USS_GND on Top Layer "USS_GND_TOP" (solid, remove dead copper, pour order 0): 1580,3490 1580,3560 1510,3560 1510,3585 1445,3650 1445,3815 1445,4155 1855,4155 1855,3650 1790,3585 1790,3560 1720,3560 1720,3490
RF_GND on Top Layer "RF_GND_TOP" (solid, remove dead copper, pour order 36): 1950,1585 1950,0 3855,0 4035,0 4035,1585

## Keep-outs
Keep-Out Layer:
  text ".Layer_Name" at 577,-858.49 h60

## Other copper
Top Layer:
  text ".Layer_Name" at 577,-858.49 h60
Bottom Layer:
  text ".Layer_Name" at 577,-858.49 h60

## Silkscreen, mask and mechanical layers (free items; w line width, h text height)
Top Overlay:
  lines w10: 2405,375 2580,375 ; 2405,475 2580,475 ; 2405,575 2580,575 ; 2405,675 2580,675 ; 2405,775 2580,775 ; 2405,880 2580,880 ; 2405,980 2580,980 ; 2405,1085 2580,1085 ; 2405,1185 2580,1185 ; 2490,285 2490,1285 ; 3430,380 3605,380 ; 3430,480 3605,480 ; 3430,580 3605,580 ; 3430,680 3605,680 ; 3430,780 3605,780 ; 3430,885 3605,885 ; 3430,985 3605,985 ; 3430,1090 3605,1090 ; 3430,1190 3605,1190 ; 3515,290 3515,1290 ; 2405,285 2580,285 2580,1285 2405,1285 2405,285 ; 3430,290 3430,1290 3605,1290 3605,290 3430,290
  text "GND" at 1877.48,4146.85 h30 r270
  text "GND" at 1967.48,4146.85 h30 r270
  text "GND" at 2052.48,4146.85 h30 r270
  text "GND" at 2142.48,4146.85 h30 r270
  text "GND" at 1955.48,4068.85 h30 r270
  text "GND" at 2040.48,4068.85 h30 r270
  text "CH1" at 2130.48,4063.85 h30 r270
  text "CH0" at 1877.48,4046.85 h30 r270
  text "GND" at 270,3685 h40
  text "V+" at 270,3590 h40
  text "<-->" at 835,2950.2 h40 r90
  text "External / ezFET / JTAG" at 855,2920.2 h40
  text "COMM_SCL" at 1530,2520 h40 r270
  text "COMM_SDA" at 1630,2520 h40 r270
  text "COMM_IRQ" at 1730,2520 h40 r270
  text "'.PRJ_Title'" at 3865,2455 h108.27 r270
  text "<-RXD" at 630,2400 h40 r270
  text "<-TXD" at 1330,2400 h40 r270
  text "->TXD" at 730,2395 h40 r270
  text "->RXD" at 1430,2395 h40 r270
  text "TEST" at 530,2360 h40 r270
  text "3V3" at 980,2330 h40 r270
  text "GND" at 1080,2330 h40 r270
  text "RST" at 430,2320 h40 r270
  text "'.PRJ_Number' / PCB Rev '.PCB_Rev'" at 3685,2275 h70 r270
  text "GND" at 2630,1830 h40 r270
  text "VCC" at 2730,1830 h40 r270
  text "NC" at 3450,1225 h35
  text "GND" at 3525,1225 h35
  text "3.3V" at 2415,1220 h35
  text "NC" at 2510,1220 h35
  text "NC" at 3450,1130 h35
  text "P7.6" at 3530,1130 h35
  text "NC" at 2425,1125 h35
  text "GND" at 2505,1125 h35
  text "P7.3" at 3530,1025 h35
  text "P8.2" at 2415,1020 h35
  text "NC" at 2510,1020 h35
  text "NC" at 3450,1020 h35
  text "NC" at 3450,925 h35
  text "NC" at 3540,925 h35
  text "P8.3" at 2415,920 h35
  text "NC" at 2510,920 h35
  text "Limited BoosterPack support." at 2635,830 h63
  text "NC" at 3450,820 h35
  text "NC" at 3540,815 h35
  text "P7.4" at 2415,810 h35
  text "NC" at 2510,810 h35
  text "NC" at 3455,720 h35
  text "P7.0" at 3530,720 h35
  text "NC" at 2425,715 h35
  text "NC" at 2510,715 h35
  text "NC" at 3455,630 h35
  text "See ti.com/tool/EVM430-FR6043 for a full list" at 2625,620 h63
  text "P7.1" at 3530,615 h35
  text "P7.2" at 2415,610 h35
  text "NC" at 2510,610 h35
  text "NC" at 3455,520 h35
  text "P8.1" at 3530,515 h35
  text "P7.7" at 2415,510 h35
  text "NC" at 2510,510 h35
  text "NC" at 3455,425 h35
  text "P8.0" at 3530,415 h35
  text "P1.7" at 2415,410 h35
  text "NC" at 2510,410 h35
  text "NC" at 3455,320 h35
  text "P7.5" at 3530,320 h35
  text "P1.6" at 2415,315 h35
  text "NC" at 2510,315 h35
  text ".Layer_Name" at 577,-858.49 h60
Bottom Overlay:
  text ".Layer_Name" at 577,-858.49 h60
Top Paste:
  text ".Layer_Name" at 577,-858.49 h60
Bottom Paste:
  text ".Layer_Name" at 577,-858.49 h60
Top Solder:
  text ".Layer_Name" at 577,-858.49 h60
  text ".Layer_Name" at 577,-858.49 h60
Bottom Solder:
  text ".Layer_Name" at 577,-858.49 h60
Drill Guide:
  text ".Layer_Name" at 577,-858.49 h60
M1 Board Outline:
  the board outline again, w10
  text ".Layer_Name" at 577,-858.49 h60
M2 Board Dimensions:
  rectangle: 0,-275 125,-150
  rectangle: 125,-400 500,-275
  lines w7: 0,-275 1000,-275 ; 125,-400 125,-150 ; 250,-400 250,-150 ; 500,-400 500,-150 ; 750,-400 750,-150 ; 0,-400 1000,-400 1000,-150 0,-150 0,-400
  lines w10: 0,-80 0,-60 ; 60,-90 0,-70 ; 60,-50 0,-70 ; 1734.09,-70 0,-70 ; 2295.91,-70 4030,-70 ; 3970,-90 4030,-70 ; 3970,-50 4030,-70 ; 4030,-80 4030,-60 ; 4065,60 4085,0 ; 4065,4340 4085,4400 ; 4075,0 4095,0 ; 4075,4400 4095,4400 ; 4085,1919.09 4085,0 ; 4085,2480.91 4085,4400 ; 4105,60 4085,0 ; 4105,4340 4085,4400
  text "4400 (mil)" at 4120.99,1929.09 h60 r90
  text "4030 (mil)" at 1744.09,-105.99 h60
  text ".Layer_Name" at 577,-858.49 h60
M3 3D STEP Top:
  text ".Layer_Name" at 577,-858.49 h60
M4 3D STEP Bottom:
  text ".Layer_Name" at 577,-858.49 h60
M5 Assembly Top:
  lines w10: -292,-930.17 6308,-930.17 ; -292,-726.83 6310,-726.83 ; -292,-523.5 -292,-1133.5 3713,-1133.5 6310,-1133.5 6310,-523.5 -291.5,-523.5 -291.5,-1133.5 1284,-1133.5 ; 2173,-1133.5 2173,-523.5 ; 3440,-726.83 3440,-523.5 ; 4280,-726.83 4280,-523.5 ; 4902,-1140 4902,-937.17
  text "COMPONENTS MARKED 'DNP' SHOULD NOT BE POPULATED." at 1153.5,-318.5 h60
  text "ASSEMBLY VARIANT:" at 1153,-434 h60
  text ".VariantName" at 2189,-434 h60
  text "PCB VIEWED FROM TOP SIDE" at -228.5,-655.67 h60
  text "BOARD #:" at 2248,-655.67 h60
  text ".PRJ_Number" at 2793.5,-655.67 h60
  text "REV:" at 3638,-655.67 h60
  text ".PCB_Rev" at 3929.5,-655.67 h60
  text "SVN REV:" at 4476,-655.67 h60
  text ".VersionControl_RevNumber" at 4982,-655.67 h60
  text "TID #:" at 2248,-859 h60
  text ".TID" at 2793.5,-859 h60
  text "PLOT NAME =" at -228.5,-1064.34 h60
  text ".plot_File_Name" at 577,-1064.34 h60
  text "GENERATED    :" at 2250,-1064.34 h60
  text ".Print_Date" at 3119.5,-1064.34 h60
  text ".Print_Time" at 3848.5,-1064.34 h60
  text "TEXAS INSTRUMENTS" at 5113,-1064.34 h60
M6 Assembly Bottom:
  lines w10: -292.5,-727.33 6309.5,-727.33 ; -290.5,-930.67 6309.5,-930.67 ; 1115.5,-1140.5 1115.5,-937.67 ; 1737.5,-727.33 1737.5,-524 ; 2577.5,-727.33 2577.5,-524 ; 3844.5,-1134 3844.5,-524 ; 4733.5,-1134 6309,-1134 6309,-524 -292.5,-524 -292.5,-1134 2304.5,-1134 6309.5,-1134 6309.5,-524
  text "COMPONENTS MARKED 'DNP' SHOULD NOT BE POPULATED." at 6102,-318 h60
  text ".VariantName" at 5058,-434 h60
  text "ASSEMBLY VARIANT:" at 6097,-434 h60
  text ".VersionControl_RevNumber" at 1035.5,-656.17 h60
  text "SVN REV:" at 1541.5,-656.17 h60
  text ".PCB_Rev" at 2088,-656.17 h60
  text "REV:" at 2379.5,-656.17 h60
  text ".PRJ_Number" at 3224,-656.17 h60
  text "BOARD #:" at 3769.5,-656.17 h60
  text "PCB VIEWED FROM BOTTOM SIDE" at 6246,-656.17 h60
  text ".TID" at 3224,-859.5 h60
  text "TID #:" at 3769.5,-859.5 h60
  text "TEXAS INSTRUMENTS" at 904.5,-1064.84 h60
  text ".Print_Time" at 2169,-1064.84 h60
  text ".Print_Date" at 2898,-1064.84 h60
  text "GENERATED    :" at 3767.5,-1064.84 h60
  text ".plot_File_Name" at 5440.5,-1064.84 h60
  text "PLOT NAME =" at 6246,-1064.84 h60
M9 Title Sheet:
  drawing of 57 lines, arcs and shapes, not listed
  text "1" at 739.84,8036.5 h70
  text "2" at 3235.5,8036.5 h70
  text "3" at 5724.84,8036.5 h70
  text "4" at 8231.51,8036.5 h70
  text "5" at 10730.5,8036.5 h70
  text "6" at 13235.5,8036.5 h70
  text "A" at -416.5,6893.5 h70
  text "A" at 14383.5,6893.5 h70
  text "B" at -416.5,4513.5 h70
  text "B" at 14383.5,4513.5 h70
  text "C" at -416.5,2138.5 h70
  text "C" at 14383.5,2138.5 h70
  text "PROJECT TITLE:" at 11343.5,277.5 h45
  text ".PRJ_Title" at 11393.5,144.17 h70
  text "DESIGNED FOR:" at 11343.5,-23.5 h45
  text ".PRJ_Customer" at 11393.5,-163.5 h70
  text "D" at -416.5,-231.5 h70
  text "D" at 14383.5,-231.5 h70
  text "FILE NAME:" at 11343.5,-323.5 h45
  text ".PCB_File_Name_No_Path" at 11393.5,-443.5 h70
  text "Texas Instruments (TI) and/or its licensors do not warrant the accuracy or completeness of this specification" at 6374,-605.34 h45
  text "ENGINEER:" at 11343.5,-613.5 h45
  text "LAYOUT BY:" at 12848.5,-613.5 h45
  text "or any information contained therein. TI and/or its licensors do not warrant that this design will meet" at 6329.01,-718 h45
  text ".PRJ_Engineer" at 11393.5,-768.49 h70
  text ".PCB_Layout" at 12899,-768.49 h70
  text "the specifications, will be suitable for your application or fit for any particular purpose, or will operate in" at 6329.01,-830.67 h45
  text ".Layer_Name" at 577,-858.49 h60
  text "ALTIUM DESIGNER VERSION:" at 12848.5,-923.5 h45
  text "an implementation. TI and/or its licensors do not warrant that the design is production worthy. You should" at 6329.01,-943.33 h45
  text "completely validate and test your design implementation to confirm the system functionality for your application." at 6374,-1056 h45
  text ".print_Scale" at 11393.5,-1056.83 h70
  text ".Application_BuildNumber" at 12899,-1056.83 h70
  text "1" at 739.84,-1263.5 h70
  text "2" at 3235.5,-1263.5 h70
  text "3" at 5724.84,-1263.5 h70
  text "4" at 8231.51,-1263.5 h70
  text "5" at 10730.5,-1263.5 h70
  text "6" at 13235.5,-1263.5 h70
M10 Fab Notes:
  drawing of 173 lines, arcs and shapes, not listed
  text "DESIGN INFORMATION" at 12378.02,6201 h60
  text "MIN. TRACK WIDTH:" at 11733.46,6021 h60
  text "8" at 12829.7,6021 h60
  text "MIL" at 12984.46,6021 h60
  text "MIN. CLEARANCE:" at 11733.46,5889 h60
  text "0.2" at 12769.7,5889 h60
  text "mm" at 12984.46,5889 h60
  text "MIN. VIA PAD SIZE:" at 11733.46,5757 h60
  text "20" at 12799.71,5757 h60
  text "MIL" at 12984.46,5757 h60
  text "0.05mm (2MIL)" at 12428.46,5615.29 h60
  text "MINIMUM ANNULAR RING" at 11404.23,5611 h60
  text "EXTERNAL" at 13136.46,5611 h60
  text "PER" at 11604.23,5493 h60
  text "IPC-D-275 CLASS 2 LEVEL C" at 11824.23,5493 h60
  text "MIL, HOLES" at 13312.46,5380.71 h60
  text "+/-" at 12920,5380 h60
  text "+/-" at 13774,5380 h60
  text "REGISTRATION TOLERANCES:" at 11404.23,5375 h60
  text "METAL" at 12604,5375 h60
  text "5" at 13180.2,5375 h60
  text "3" at 14013.2,5375 h60
  text "MIL" at 14129.46,5375 h60
  text "+/-" at 13774,5262 h60
  text "HOLE SIZE TOLERANCE (UNLESS OTHERWISE SPECIFIED):" at 11404.23,5257 h60
  text "3" at 14013.2,5257 h60
  text "MIL" at 14129.46,5257 h60
  text "MATERIAL:" at 11329.46,5047.54 h60
  text "FR-4 High Tg" at 12315.9,4907.21 h60
  text "FR-408" at 11750.46,4898.64 h60
  text "OTHER" at 13238.46,4898.64 h60
  text "X" at 12161,4895 h60
  text "62 MIL (1.6mm) +/-10%" at 12070.56,4735.92 h60
  text "THICKNESS:" at 11404.23,4731.64 h60
  text "X" at 11942.4,4731.64 h60
  text "OTHER" at 13355.46,4731.64 h60
  text "TOLERANCE:" at 11404.23,4573.64 h60
  text "X" at 12243.53,4573.64 h60
  text "ANSI IPC-6012 TYPE 3 CLASS 2" at 12430.48,4573.64 h60
  text "OTHER +/-" at 12430.46,4417.64 h60
  text "BOW & TWIST:" at 11404.23,4260.64 h60
  text "X" at 12243.53,4260.64 h60
  text "ANSI IPC-6012 TYPE 3 CLASS 2" at 12430.48,4260.64 h60
  text "OTHER +/-" at 12430.46,4102.13 h60
  text "DRILLING:" at 11329.46,3963.64 h60
  text "REFERENCE:" at 11404.23,3846.64 h60
  text "X" at 12052.46,3846.64 h60
  text "AS SHOWN" at 12239.46,3846.64 h60
  text "X" at 12953.46,3846.64 h60
  text "NC_DRILL FILES" at 13090.46,3846.64 h60
  text "PTH COPPER THICKNESS:" at 11404.23,3688.64 h60
  text "X" at 12534.46,3688.64 h60
  text "20-30 um" at 12671.46,3688.64 h60
  text "OTHER" at 13388.46,3688.64 h60
  text "BOARD FINISH:" at 11329.46,3529.64 h60
  text "SILKSCREEN:" at 11484.68,3411.64 h60
  text "X" at 12433.46,3411.64 h60
  text "TOP" at 12559.46,3411.64 h60
  text "BOTTOM" at 13070.46,3411.64 h60
  text "SILKSCREEN COLOR:" at 11484.68,3244.64 h60
  text "X" at 12432.42,3244.64 h60
  text "WHITE" at 12559.46,3244.64 h60
  text "OTHER" at 13070.46,3244.64 h60
  text "GREEN" at 12690.46,3085.44 h60
  text "X" at 13148.42,3085.44 h60
  text "OTHER" at 13308.46,3085.44 h60
  text "SOLDER RESIST COLOR:" at 11484.68,3074.64 h60
  text "RED" at 13798.46,3070.44 h60
  text "X" at 12563.42,2915.44 h60
  text "MATTE" at 12690.46,2915.44 h60
  text "SEMI-GLOSS" at 13308,2914.8 h60
  text "IMMERSION GOLD (ENIG)" at 12390.46,2726.92 h60
  text "ENEPIG" at 13728,2723.64 h60
  text "SURFACE FINISH:" at 11329.46,2722.64 h60
  text "X" at 12203.51,2722.64 h60
  text "IMM. TIN/SILVER OR EQUIV" at 11659,2565.64 h60
  text "OTHER" at 13090.46,2565.64 h60
  text "ARRAY/PANEL:" at 11329.46,2386.64 h60
  text "CUT AND TRIM PER M1 BOARD OUTLINE" at 12390.46,2382.35 h60
  text "N.C. ROUTE" at 12390.46,2230.64 h60
  text "X" at 13069.46,2230.64 h60
  text "V. SCORE" at 13256.46,2230.64 h60
  text "CERTIFICATION:" at 11329.46,2093.64 h60
  text "MATERIALS AND WORKMANSHIP FOR ALL PCBS" at 12054.46,2093.64 h60
  text "TO MEET OR EXCEED THE REQUIREMENTS OF:" at 12054.46,1995.64 h60
  text "X" at 11680.96,1859.13 h60
  text "ANSI IPC-A-600F CLASS ->" at 11819.96,1859.13 h60
  text "X" at 13459.02,1859.13 h60
  text "2" at 13577.96,1859.14 h60
  text "1" at 13262.96,1857.64 h60
  text "3" at 13931.96,1857.64 h60
  text "X" at 12495.02,1699.64 h60
  text "RoHS" at 12631.96,1699.64 h60
  text "OTHER" at 13276.36,1699.64 h60
  text "PER ORDER" at 13673.42,1699.64 h60
  text "ALL BOARDS MUST MEET OR EXCEED UL94-V0 REQUIREMENTS." at 11357,1534 h60
  text "PCB MUST BEAR THE UL94V-0 UL REGISTERED MATERIAL ID NUMBER" at 11357,1414 h60
  text "ADDITIONAL REQUIREMENTS:" at 11329.46,1240.64 h60
  text "MICROSECTION:" at 11404.23,1125.64 h60
  text "YES" at 12309.96,1125.64 h60
  text "REQUIRED" at 13171.46,969.49 h60
  text "BARE BOARD ELEC. TEST:" at 11404.23,966.64 h60
  text "NONE" at 12709.96,966.64 h60
  text "X" at 13044.46,966.64 h60
  text "PER ORDER" at 13763.46,966.64 h60
  text ".Layer_Name" at 577,-858.49 h60
M11 Gerber Information:
  lines w10: -292,-930.17 6308,-930.17 ; -292,-726.83 6310,-726.83 ; -292,-523.5 -292,-1133.5 3713,-1133.5 6310,-1133.5 6310,-523.5 -291.5,-523.5 -291.5,-1133.5 1284,-1133.5 ; 2173,-1133.5 2173,-523.5 ; 3440,-726.83 3440,-523.5 ; 4280,-726.83 4280,-523.5 ; 4902,-1140 4902,-937.17
  text "ALL ARTWORK VIEWED FROM TOP SIDE" at -228.5,-655.67 h60
  text "BOARD #:" at 2248,-655.67 h60
  text ".PRJ_Number" at 2793.5,-655.67 h60
  text "REV:" at 3638,-655.67 h60
  text ".PCB_Rev" at 3929.5,-655.67 h60
  text "SVN REV:" at 4476,-655.67 h60
  text ".VersionControl_RevNumber" at 4982,-655.67 h60
  text "LAYER NAME =" at -228.5,-858.49 h60
  text "TID #:" at 2248,-859 h60
  text ".TID" at 2793.5,-859 h60
  text "PLOT NAME =" at -228.5,-1064.34 h60
  text ".plot_File_Name" at 577,-1064.34 h60
  text "GENERATED    :" at 2250,-1064.34 h60
  text ".Print_Date" at 3119.5,-1064.34 h60
  text ".Print_Time" at 3848.5,-1064.34 h60
  text "TEXAS INSTRUMENTS" at 5113,-1064.34 h60
M12 Stackup:
  drawing of 191 lines, arcs and shapes, not listed
  text "Layer" at 9797.84,7830 h60
  text "Name" at 10207.76,7830 h60
  text "Material" at 11137.5,7830 h60
  text "Thickness" at 11997.27,7830 h60
  text "Constant" at 12647.1,7830 h60
  text "Board Layer Stack" at 13216.96,7830 h60
  text "1" at 9797.84,7710 h60
  text "Top Overlay" at 10207.76,7710 h60
  text "2" at 9797.84,7590 h60
  text "Top Solder" at 10207.76,7590 h60
  text "Solder Resist" at 11137.5,7590 h60
  text "0.40mil" at 11997.27,7590 h60
  text "3.5" at 12647.1,7590 h60
  text "3" at 9797.84,7470 h60
  text "Top Layer" at 10207.76,7470 h60
  text "Copper" at 11137.5,7470 h60
  text "1.40mil" at 11997.27,7470 h60
  text "4" at 9797.84,7350 h60
  text "Dielectric1" at 10207.76,7350 h60
  text "FR-4" at 11137.5,7350 h60
  text "59.20mil" at 11997.27,7350 h60
  text "4.8" at 12647.1,7350 h60
  text "5" at 9797.84,7230 h60
  text "Bottom Layer" at 10207.76,7230 h60
  text "Copper" at 11137.5,7230 h60
  text "1.40mil" at 11997.27,7230 h60
  text "6" at 9797.84,7110 h60
  text "Bottom Solder" at 10207.76,7110 h60
  text "Solder Resist" at 11137.5,7110 h60
  text "0.40mil" at 11997.27,7110 h60
  text "3.5" at 12647.1,7110 h60
  text "7" at 9797.84,6990 h60
  text "Bottom Overlay" at 10207.76,6990 h60
  text ".Layer_Name" at 577,-858.49 h60
M13 Component Bodies Top:
  text ".Layer_Name" at 577,-858.49 h60
M14 Component Bodies Bottom:
  text ".Layer_Name" at 577,-858.49 h60
M15 Courtyards Top:
  text ".Layer_Name" at 577,-858.49 h60
M16 Courtyards Bottom:
  text ".Layer_Name" at 577,-858.49 h60
Drill Drawing:
  circle w10: c8169.6,3914.16 r27.59
  circle w10: c8169.6,3169.17 r16.56
  circle w10: c8169.6,3169.17 r27.59
  lines w10: 8142.01,2948.43 8197.2,2948.43 8169.6,2893.24 8142.01,2948.43 ; 8142.01,3031.21 8155.81,3031.21 8169.6,3017.41 8183.4,3031.21 8197.2,3031.21 8183.4,3045 8197.2,3058.8 8183.4,3058.8 8169.6,3072.59 8155.81,3058.8 8142.01,3058.8 8155.81,3045 8142.01,3031.21 ; 8142.01,3265.74 8142.01,3279.54 8155.81,3293.33 8142.01,3307.13 8142.01,3320.92 8155.81,3320.92 8169.6,3307.13 8183.4,3320.92 8197.2,3320.92 8197.2,3307.13 8183.4,3293.33 8197.2,3279.54 8197.2,3265.74 8183.4,3265.74 8169.6,3279.54 8155.81,3265.74 8142.01,3265.74 ; 8142.01,3417.5 8169.6,3389.9 8197.2,3417.5 8169.6,3445.09 8142.01,3417.5 ; 8142.01,3514.07 8197.2,3514.07 8197.2,3569.25 8142.01,3569.25 8142.01,3514.07 ; 8142.01,3638.23 8197.2,3638.23 8197.2,3693.42 8142.01,3693.42 8142.01,3638.23 ; 8142.01,3762.4 8169.6,3776.2 8197.2,3762.4 8183.4,3789.99 8197.2,3817.58 8169.6,3803.79 8142.01,3817.58 8155.81,3789.99 8142.01,3762.4 ; 8142.01,4065.91 8197.2,4065.91 8169.6,4010.73 8142.01,4065.91 ; 8153.05,2937.39 8186.16,2937.39 8169.6,2904.28 8153.05,2937.39 ; 8153.05,3649.27 8186.16,3649.27 8186.16,3682.38 8153.05,3682.38 8153.05,3649.27
  lines w12: 8091.98,2855.99 11321.64,2855.99 ; 8091.98,4097.65 11321.64,4097.65 ; 8429.62,2731.83 8429.62,4221.81 ; 8761.64,2731.83 8761.64,4221.81 ; 9398.11,2731.83 9398.11,4221.81 ; 9657.15,2731.83 9657.15,4221.81 ; 10032.26,2731.83 10032.26,4221.81 ; 10755.27,2731.83 10755.27,4221.81 ; 8091.98,2731.83 11321.64,2731.83 11321.64,4221.81 8091.98,4221.81 8091.98,2731.83
  text "Symbol" at 8166.48,4134.89 h72
  text "Quantity" at 8466.87,4134.89 h72
  text "Finished Hole Size" at 8798.89,4134.89 h72
  text "Plated" at 9435.36,4134.89 h72
  text "Hole Type" at 9694.4,4134.89 h72
  text "Drill Layer Pair" at 10069.51,4134.89 h72
  text "Hole Tolerance" at 10792.52,4134.89 h72
  text "43" at 8466.87,4010.73 h60
  text "7.87mil (0.200mm)" at 8798.89,4010.73 h60
  text "PTH" at 9435.36,4010.73 h60
  text "Round" at 9694.4,4010.73 h60
  text "Top Layer - Bottom Layer" at 10069.51,4010.73 h60
  text "525" at 8466.87,3886.56 h60
  text "11.81mil (0.300mm)" at 8798.89,3886.56 h60
  text "PTH" at 9435.36,3886.56 h60
  text "Round" at 9694.4,3886.56 h60
  text "Top Layer - Bottom Layer" at 10069.51,3886.56 h60
  text "4" at 8466.87,3762.4 h60
  text "31.50mil (0.800mm)" at 8798.89,3762.4 h60
  text "PTH" at 9435.36,3762.4 h60
  text "Round" at 9694.4,3762.4 h60
  text "Top Layer - Bottom Layer" at 10069.51,3762.4 h60
  text "38" at 8466.87,3638.23 h60
  text "35.43mil (0.900mm)" at 8798.89,3638.23 h60
  text "PTH" at 9435.36,3638.23 h60
  text "Round" at 9694.4,3638.23 h60
  text "Top Layer - Bottom Layer" at 10069.51,3638.23 h60
  text "94" at 8466.87,3514.07 h60
  text "40.00mil (1.016mm)" at 8798.89,3514.07 h60
  text "PTH" at 9435.36,3514.07 h60
  text "Round" at 9694.4,3514.07 h60
  text "Top Layer - Bottom Layer" at 10069.51,3514.07 h60
  text "4" at 8466.87,3389.9 h60
  text "40.16mil (1.020mm)" at 8798.89,3389.9 h60
  text "PTH" at 9435.36,3389.9 h60
  text "Round" at 9694.4,3389.9 h60
  text "Top Layer - Bottom Layer" at 10069.51,3389.9 h60
  text "13" at 8466.87,3265.74 h60
  text "45.28mil (1.150mm)" at 8798.89,3265.74 h60
  text "PTH" at 9435.36,3265.74 h60
  text "Round" at 9694.4,3265.74 h60
  text "Top Layer - Bottom Layer" at 10069.51,3265.74 h60
  text "4" at 8466.87,3141.57 h60
  text "47.24mil (1.200mm)" at 8798.89,3141.57 h60
  text "PTH" at 9435.36,3141.57 h60
  text "Round" at 9694.4,3141.57 h60
  text "Top Layer - Bottom Layer" at 10069.51,3141.57 h60
  text "2" at 8466.87,3017.41 h60
  text "49.21mil (1.250mm)" at 8798.89,3017.41 h60
  text "PTH" at 9435.36,3017.41 h60
  text "Round" at 9694.4,3017.41 h60
  text "Top Layer - Bottom Layer" at 10069.51,3017.41 h60
  text "2" at 8466.87,2893.24 h60
  text "23.62mil (0.600mm)" at 8798.89,2893.24 h60
  text "PTH" at 9435.36,2893.24 h60
  text "Slot" at 9694.4,2893.24 h60
  text "Top Layer - Bottom Layer" at 10069.51,2893.24 h60
  text "729 Total" at 8466.87,2769.08 h60
  text "Slot definitions :" at 8166.48,2682.16 h60
  text "Routed Path Length" at 8616.22,2682.16 h60
  text "= Calculated from tool start centre position to tool end centre position." at 9154.84,2682.16 h60
  text "Hole Length" at 8616.22,2632.5 h60
  text "= Routed Path Length + Tool Size = Slot length as defined in the PCB layout" at 8955.45,2632.5 h60
  text ".Layer_Name" at 577,-858.49 h60

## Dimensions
0,-400 to 1000,-400 on M2 Board Dimensions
